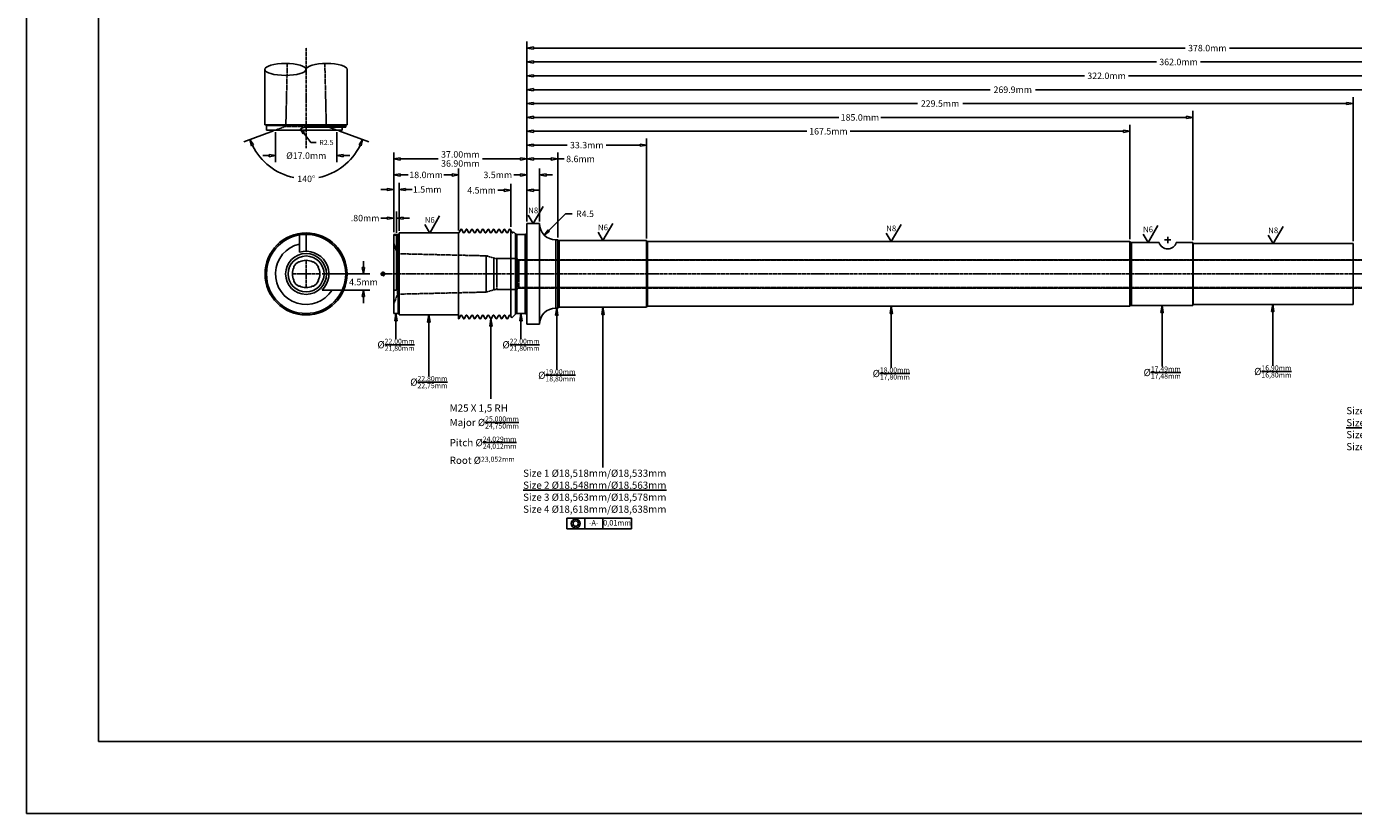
# Model space of a CAD drawing. Units: inches. Extents: x 0 to 594, y 0 to 420.
# Drawn here: x 0 to 369, y 0 to 219 of the extents above; entities that cross this region are included whole.
import ezdxf
from ezdxf.enums import TextEntityAlignment as Align

# ---------------------------------------------------------------- set-up
doc = ezdxf.new("R2010")
doc.units = ezdxf.units.IN
doc.header["$MEASUREMENT"] = 0
doc.linetypes.add('CENTER2', pattern=[1.125, 0.75, -0.125, 0.125, -0.125])
doc.linetypes.add('HIDDEN2', pattern=[0.1875, 0.125, -0.0625])
for name, color, linetype in [('CENTER', 1, 'CENTER2'), ('CENTERLINE', 1, 'CENTER2'), ('HIDDEN', 5, 'HIDDEN2'), ('TEXT', 5, 'Continuous')]:
    doc.layers.add(name, color=color, linetype=linetype)
doc.dimstyles.get("Standard").update_dxf_attribs({"dimscale": 10, "dimtxt": 0.18, "dimasz": 0.18, "dimexe": 0.18, "dimexo": 0.0625, "dimgap": 0.09, "dimtad": 0, "dimtih": 1, "dimtoh": 1, "dimdec": 4, "dimzin": 0, "dimdsep": 46, "dimtxsty": 'Standard', "dimblk": 'CLOSEDBLANK', "dimcen": 0.09, "dimadec": 4, "dimazin": 0, "dimtfac": 1, "dimtdec": 4, "dimtofl": 0, "dimtmove": 0, "dimatfit": 3, "dimldrblk": 'CLOSEDBLANK', "dimfxl": 0, "dimtolj": 1, "dimtzin": 0, "dimarcsym": 0})
doc.dimstyles.new('Standard$0', dxfattribs={"dimscale": 10, "dimtxt": 0.18, "dimasz": 0.18, "dimexe": 0.18, "dimexo": 0.0625, "dimgap": 0.09, "dimtad": 0, "dimtih": 1, "dimtoh": 1, "dimdec": 4, "dimzin": 4, "dimdsep": 46, "dimtxsty": 'Standard', "dimblk": 'CLOSEDBLANK', "dimcen": 0.09, "dimadec": 5, "dimazin": 1, "dimtfac": 1, "dimtdec": 4, "dimtofl": 0, "dimtmove": 0, "dimatfit": 3, "dimldrblk": 'CLOSEDBLANK', "dimfxl": 0, "dimtolj": 1, "dimtzin": 0, "dimarcsym": 0})

# ---------------------------------------------------------------- blocks, each defined once
blk = doc.blocks.new('_ClosedBlank')
at = {"color": 0, "linetype": 'ByBlock', "lineweight": -2}
for p, q in [((-1, 0.17), (0, 0)), ((-1, 0.17), (-1, -0.17)), ((0, 0), (-1, -0.17))]:
    blk.add_line(p, q, dxfattribs=at)
blk = doc.blocks.new('*D20')
at = {"color": 0, "lineweight": -2}
for p, q in [((139, 164.63), (139, 210.74)), ((501, 157.15), (501, 210.74)), ((140.8, 208.94), (313.85, 208.94)), ((499.2, 208.94), (326.15, 208.94))]:
    blk.add_line(p, q, dxfattribs=at)
at = {"layer": 'Defpoints', "color": 0}
for p in [(501, 208.94), (139, 164), (501, 156.53)]:
    blk.add_point(p, dxfattribs=at)
at = {"color": 0, "lineweight": -2, "xscale": 1.8, "yscale": 1.8, "zscale": 1.8, "rotation": 180}
blk.add_blockref('_ClosedBlank', (139, 208.94), dxfattribs=at)
at = {"color": 0, "lineweight": -2, "xscale": 1.8, "yscale": 1.8, "zscale": 1.8}
blk.add_blockref('_ClosedBlank', (501, 208.94), dxfattribs=at)
at = {"color": 0, "insert": (320, 208.94), "char_height": 1.8, "attachment_point": 5}
blk.add_mtext('\\A1;362.0mm', dxfattribs=at)
blk = doc.blocks.new('*D7')
at = {"color": 0, "lineweight": -2}
for p, q in [((102, 161.63), (102, 167.33)), ((102.8, 161.43), (102.8, 167.33)), ((100.2, 165.53), (98.4, 165.53)), ((104.6, 165.53), (106.4, 165.53))]:
    blk.add_line(p, q, dxfattribs=at)
at = {"layer": 'Defpoints', "color": 0}
for p in [(102.8, 165.53), (102, 161), (102.8, 160.8)]:
    blk.add_point(p, dxfattribs=at)
at = {"color": 0, "lineweight": -2, "xscale": 1.8, "yscale": 1.8, "zscale": 1.8}
blk.add_blockref('_ClosedBlank', (102, 165.53), dxfattribs=at)
at = {"color": 0, "lineweight": -2, "xscale": 1.8, "yscale": 1.8, "zscale": 1.8, "rotation": 180}
blk.add_blockref('_ClosedBlank', (102.8, 165.53), dxfattribs=at)
at = {"color": 0, "insert": (94.05, 165.53), "char_height": 1.8, "attachment_point": 5}
blk.add_mtext('\\A1;.80mm', dxfattribs=at)
blk = doc.blocks.new('*D8')
at = {"color": 0, "lineweight": -2}
for p, q in [((100.2, 173.5), (98.4, 173.5)), ((102, 161.63), (102, 175.3)), ((103.5, 162.03), (103.5, 175.3)), ((105.3, 173.5), (107.1, 173.5))]:
    blk.add_line(p, q, dxfattribs=at)
at = {"layer": 'Defpoints', "color": 0}
for p in [(103.5, 173.5), (102, 161), (103.5, 161.4)]:
    blk.add_point(p, dxfattribs=at)
at = {"color": 0, "lineweight": -2, "xscale": 1.8, "yscale": 1.8, "zscale": 1.8}
blk.add_blockref('_ClosedBlank', (102, 173.5), dxfattribs=at)
at = {"color": 0, "lineweight": -2, "xscale": 1.8, "yscale": 1.8, "zscale": 1.8, "rotation": 180}
blk.add_blockref('_ClosedBlank', (103.5, 173.5), dxfattribs=at)
at = {"color": 0, "insert": (111.3, 173.5), "char_height": 1.8, "attachment_point": 5}
blk.add_mtext('\\A1;1.5mm', dxfattribs=at)
blk = doc.blocks.new('*D9')
at = {"color": 0, "lineweight": -2}
for p, q in [((102, 161.63), (102, 179.34)), ((103.8, 177.54), (106.05, 177.54)), ((118.2, 177.54), (115.95, 177.54)), ((120, 162.1), (120, 179.34))]:
    blk.add_line(p, q, dxfattribs=at)
at = {"layer": 'Defpoints', "color": 0}
for p in [(120, 177.54), (102, 161), (120, 161.47)]:
    blk.add_point(p, dxfattribs=at)
at = {"color": 0, "lineweight": -2, "xscale": 1.8, "yscale": 1.8, "zscale": 1.8, "rotation": 180}
blk.add_blockref('_ClosedBlank', (102, 177.54), dxfattribs=at)
at = {"color": 0, "lineweight": -2, "xscale": 1.8, "yscale": 1.8, "zscale": 1.8}
blk.add_blockref('_ClosedBlank', (120, 177.54), dxfattribs=at)
at = {"color": 0, "insert": (111, 177.54), "char_height": 1.8, "attachment_point": 5}
blk.add_mtext('\\A1;18.0mm', dxfattribs=at)
blk = doc.blocks.new('*D10')
at = {"color": 0, "lineweight": -2}
for p, q in [((102, 161.63), (102, 183.78)), ((103.8, 181.98), (114.35, 181.98)), ((137.2, 181.98), (126.65, 181.98)), ((139, 164.63), (139, 183.78))]:
    blk.add_line(p, q, dxfattribs=at)
at = {"layer": 'Defpoints', "color": 0}
for p in [(102, 181.98), (139, 164), (102, 161)]:
    blk.add_point(p, dxfattribs=at)
at = {"color": 0, "lineweight": -2, "xscale": 1.8, "yscale": 1.8, "zscale": 1.8, "rotation": 180}
blk.add_blockref('_ClosedBlank', (102, 181.98), dxfattribs=at)
at = {"color": 0, "lineweight": -2, "xscale": 1.8, "yscale": 1.8, "zscale": 1.8}
blk.add_blockref('_ClosedBlank', (139, 181.98), dxfattribs=at)
at = {"color": 0, "insert": (120.5, 181.98), "char_height": 1.8, "attachment_point": 5}
blk.add_mtext('\\A1;\\S37.00mm^ 36.90mm;', dxfattribs=at)
blk = doc.blocks.new('*D11')
at = {"color": 0, "lineweight": -2}
for p, q in [((137.2, 177.54), (135.4, 177.54)), ((139, 164.63), (139, 179.34)), ((142.5, 164.63), (142.5, 179.34)), ((144.3, 177.54), (146.1, 177.54))]:
    blk.add_line(p, q, dxfattribs=at)
at = {"layer": 'Defpoints', "color": 0}
for p in [(139, 177.54), (139, 164), (142.5, 164)]:
    blk.add_point(p, dxfattribs=at)
at = {"color": 0, "lineweight": -2, "xscale": 1.8, "yscale": 1.8, "zscale": 1.8}
blk.add_blockref('_ClosedBlank', (139, 177.54), dxfattribs=at)
at = {"color": 0, "lineweight": -2, "xscale": 1.8, "yscale": 1.8, "zscale": 1.8, "rotation": 180}
blk.add_blockref('_ClosedBlank', (142.5, 177.54), dxfattribs=at)
at = {"color": 0, "insert": (130.9, 177.54), "char_height": 1.8, "attachment_point": 5}
blk.add_mtext('\\A1;3.5mm', dxfattribs=at)
blk = doc.blocks.new('*D12')
at = {"color": 0, "lineweight": -2}
for p, q in [((139, 164.63), (139, 183.78)), ((140.8, 181.98), (145.78, 181.98)), ((147.58, 160.13), (147.58, 183.78)), ((147.58, 181.98), (149.38, 181.98))]:
    blk.add_line(p, q, dxfattribs=at)
at = {"layer": 'Defpoints', "color": 0}
for p in [(147.58, 181.98), (139, 164), (147.58, 159.5)]:
    blk.add_point(p, dxfattribs=at)
at = {"color": 0, "lineweight": -2, "xscale": 1.8, "yscale": 1.8, "zscale": 1.8, "rotation": 180}
blk.add_blockref('_ClosedBlank', (139, 181.98), dxfattribs=at)
at = {"color": 0, "lineweight": -2, "xscale": 1.8, "yscale": 1.8, "zscale": 1.8}
blk.add_blockref('_ClosedBlank', (147.58, 181.98), dxfattribs=at)
at = {"color": 0, "insert": (153.88, 181.98), "char_height": 1.8, "attachment_point": 5}
blk.add_mtext('\\A1;8.6mm', dxfattribs=at)
blk = doc.blocks.new('*D13')
at = {"color": 0, "lineweight": -2}
for p, q in [((139, 164.63), (139, 187.62)), ((140.8, 185.82), (150.22, 185.82)), ((170.45, 185.82), (161.02, 185.82)), ((172.25, 159.9), (172.25, 187.62))]:
    blk.add_line(p, q, dxfattribs=at)
at = {"layer": 'Defpoints', "color": 0}
for p in [(139, 185.82), (139, 164), (172.25, 159.28)]:
    blk.add_point(p, dxfattribs=at)
at = {"color": 0, "lineweight": -2, "xscale": 1.8, "yscale": 1.8, "zscale": 1.8, "rotation": 180}
blk.add_blockref('_ClosedBlank', (139, 185.82), dxfattribs=at)
at = {"color": 0, "lineweight": -2, "xscale": 1.8, "yscale": 1.8, "zscale": 1.8}
blk.add_blockref('_ClosedBlank', (172.25, 185.82), dxfattribs=at)
at = {"color": 0, "insert": (155.62, 185.82), "char_height": 1.8, "attachment_point": 5}
blk.add_mtext('\\A1;33.3mm', dxfattribs=at)
blk = doc.blocks.new('*D14')
at = {"color": 0, "lineweight": -2}
for p, q in [((139, 164.63), (139, 191.47)), ((140.8, 189.67), (216.75, 189.67)), ((304.7, 189.67), (228.75, 189.67)), ((306.5, 159.63), (306.5, 191.47))]:
    blk.add_line(p, q, dxfattribs=at)
at = {"layer": 'Defpoints', "color": 0}
for p in [(139, 189.67), (139, 164), (306.5, 159)]:
    blk.add_point(p, dxfattribs=at)
at = {"color": 0, "lineweight": -2, "xscale": 1.8, "yscale": 1.8, "zscale": 1.8, "rotation": 180}
blk.add_blockref('_ClosedBlank', (139, 189.67), dxfattribs=at)
at = {"color": 0, "lineweight": -2, "xscale": 1.8, "yscale": 1.8, "zscale": 1.8}
blk.add_blockref('_ClosedBlank', (306.5, 189.67), dxfattribs=at)
at = {"color": 0, "insert": (222.75, 189.67), "char_height": 1.8, "attachment_point": 5}
blk.add_mtext('\\A1;167.5mm', dxfattribs=at)
blk = doc.blocks.new('*D15')
at = {"color": 0, "lineweight": -2}
for p, q in [((139, 164.63), (139, 195.33)), ((140.8, 193.53), (225.65, 193.53)), ((322.2, 193.53), (237.35, 193.53)), ((324, 159.35), (324, 195.33))]:
    blk.add_line(p, q, dxfattribs=at)
at = {"layer": 'Defpoints', "color": 0}
for p in [(139, 193.53), (139, 164), (324, 158.73)]:
    blk.add_point(p, dxfattribs=at)
at = {"color": 0, "lineweight": -2, "xscale": 1.8, "yscale": 1.8, "zscale": 1.8, "rotation": 180}
blk.add_blockref('_ClosedBlank', (139, 193.53), dxfattribs=at)
at = {"color": 0, "lineweight": -2, "xscale": 1.8, "yscale": 1.8, "zscale": 1.8}
blk.add_blockref('_ClosedBlank', (324, 193.53), dxfattribs=at)
at = {"color": 0, "insert": (231.5, 193.53), "char_height": 1.8, "attachment_point": 5}
blk.add_mtext('\\A1;185.0mm', dxfattribs=at)
blk = doc.blocks.new('*D16')
at = {"color": 0, "lineweight": -2}
for p, q in [((139, 164.63), (139, 199.18)), ((368.5, 159.08), (368.5, 199.18)), ((140.8, 197.38), (247.45, 197.38)), ((366.7, 197.38), (260.05, 197.38))]:
    blk.add_line(p, q, dxfattribs=at)
at = {"layer": 'Defpoints', "color": 0}
for p in [(139, 197.38), (139, 164), (368.5, 158.45)]:
    blk.add_point(p, dxfattribs=at)
at = {"color": 0, "lineweight": -2, "xscale": 1.8, "yscale": 1.8, "zscale": 1.8, "rotation": 180}
blk.add_blockref('_ClosedBlank', (139, 197.38), dxfattribs=at)
at = {"color": 0, "lineweight": -2, "xscale": 1.8, "yscale": 1.8, "zscale": 1.8}
blk.add_blockref('_ClosedBlank', (368.5, 197.38), dxfattribs=at)
at = {"color": 0, "insert": (253.75, 197.38), "char_height": 1.8, "attachment_point": 5}
blk.add_mtext('\\A1;229.5mm', dxfattribs=at)
blk = doc.blocks.new('*D17')
at = {"color": 0, "lineweight": -2}
for p, q in [((139, 164.63), (139, 206.89)), ((461, 158.38), (461, 206.89)), ((140.8, 205.09), (293.85, 205.09)), ((459.2, 205.09), (306.15, 205.09))]:
    blk.add_line(p, q, dxfattribs=at)
at = {"layer": 'Defpoints', "color": 0}
for p in [(461, 205.09), (139, 164), (461, 157.75)]:
    blk.add_point(p, dxfattribs=at)
at = {"color": 0, "lineweight": -2, "xscale": 1.8, "yscale": 1.8, "zscale": 1.8, "rotation": 180}
blk.add_blockref('_ClosedBlank', (139, 205.09), dxfattribs=at)
at = {"color": 0, "lineweight": -2, "xscale": 1.8, "yscale": 1.8, "zscale": 1.8}
blk.add_blockref('_ClosedBlank', (461, 205.09), dxfattribs=at)
at = {"color": 0, "insert": (300, 205.09), "char_height": 1.8, "attachment_point": 5}
blk.add_mtext('\\A1;322.0mm', dxfattribs=at)
blk = doc.blocks.new('*D22')
at = {"color": 0, "lineweight": -2}
for p, q in [((93.58, 151.8), (93.58, 153.6)), ((82.08, 150), (95.38, 150)), ((88.31, 145.5), (95.38, 145.5)), ((93.58, 143.7), (93.58, 141.9))]:
    blk.add_line(p, q, dxfattribs=at)
at = {"layer": 'Defpoints', "color": 0}
for p in [(81.46, 150), (93.58, 150), (87.69, 145.5)]:
    blk.add_point(p, dxfattribs=at)
at = {"color": 0, "lineweight": -2, "xscale": 1.8, "yscale": 1.8, "zscale": 1.8}
for p, rotation in [((93.58, 150), 270), ((93.58, 145.5), 90)]:
    blk.add_blockref('_ClosedBlank', p, dxfattribs=dict(at, rotation=rotation))
at = {"color": 0, "insert": (93.58, 147.75), "char_height": 1.8, "attachment_point": 5}
blk.add_mtext('\\A1;4.5mm', dxfattribs=at)
blk = doc.blocks.new('*D23')
at = {"color": 0, "lineweight": -2}
for p, q in [((78.99, 186.56), (77, 189.14)), ((80.43, 186.56), (78.99, 186.56))]:
    blk.add_line(p, q, dxfattribs=at)
at = {"layer": 'Defpoints', "color": 0}
for p in [(76.12, 190.28), (77.65, 188.3)]:
    blk.add_point(p, dxfattribs=at)
at = {"color": 0, "lineweight": -2, "xscale": 1.44, "yscale": 1.44, "zscale": 1.44, "rotation": 127.7379653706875}
blk.add_blockref('_ClosedBlank', (76.12, 190.28), dxfattribs=at)
at = {"color": 0, "insert": (83.31, 186.56), "char_height": 1.44, "attachment_point": 5}
blk.add_mtext('\\A1;R2.5', dxfattribs=at)
blk = doc.blocks.new('*D24')
at = {"color": 0, "lineweight": -2}
for p, q in [((139, 164.63), (139, 203.03)), ((408.9, 158.65), (408.9, 203.03)), ((140.8, 201.23), (267.65, 201.23)), ((407.1, 201.23), (280.25, 201.23))]:
    blk.add_line(p, q, dxfattribs=at)
at = {"layer": 'Defpoints', "color": 0}
for p in [(139, 201.23), (139, 164), (408.9, 158.03)]:
    blk.add_point(p, dxfattribs=at)
at = {"color": 0, "lineweight": -2, "xscale": 1.8, "yscale": 1.8, "zscale": 1.8, "rotation": 180}
blk.add_blockref('_ClosedBlank', (139, 201.23), dxfattribs=at)
at = {"color": 0, "lineweight": -2, "xscale": 1.8, "yscale": 1.8, "zscale": 1.8}
blk.add_blockref('_ClosedBlank', (408.9, 201.23), dxfattribs=at)
at = {"color": 0, "insert": (273.95, 201.23), "char_height": 1.8, "attachment_point": 5}
blk.add_mtext('\\A1;269.9mm', dxfattribs=at)
blk = doc.blocks.new('*D25')
at = {"color": 0, "lineweight": -2}
for p, q in [((139, 164.63), (139, 214.6)), ((517, 157.52), (517, 214.6)), ((140.8, 212.8), (321.85, 212.8)), ((515.2, 212.8), (334.15, 212.8))]:
    blk.add_line(p, q, dxfattribs=at)
at = {"layer": 'Defpoints', "color": 0}
for p in [(517, 212.8), (139, 164), (517, 156.89)]:
    blk.add_point(p, dxfattribs=at)
at = {"color": 0, "lineweight": -2, "xscale": 1.8, "yscale": 1.8, "zscale": 1.8, "rotation": 180}
blk.add_blockref('_ClosedBlank', (139, 212.8), dxfattribs=at)
at = {"color": 0, "lineweight": -2, "xscale": 1.8, "yscale": 1.8, "zscale": 1.8}
blk.add_blockref('_ClosedBlank', (517, 212.8), dxfattribs=at)
at = {"color": 0, "insert": (328, 212.8), "char_height": 1.8, "attachment_point": 5}
blk.add_mtext('\\A1;378.0mm', dxfattribs=at)
blk = doc.blocks.new('*D26')
at = {"color": 0, "lineweight": -2}
for p, q in [((132.7, 173.26), (130.9, 173.26)), ((134.5, 163.13), (134.5, 175.06)), ((139, 164.63), (139, 175.06)), ((140.8, 173.26), (142.6, 173.26))]:
    blk.add_line(p, q, dxfattribs=at)
at = {"layer": 'Defpoints', "color": 0}
for p in [(139, 173.26), (134.5, 162.5), (139, 164)]:
    blk.add_point(p, dxfattribs=at)
at = {"color": 0, "lineweight": -2, "xscale": 1.8, "yscale": 1.8, "zscale": 1.8}
blk.add_blockref('_ClosedBlank', (134.5, 173.26), dxfattribs=at)
at = {"color": 0, "lineweight": -2, "xscale": 1.8, "yscale": 1.8, "zscale": 1.8, "rotation": 180}
blk.add_blockref('_ClosedBlank', (139, 173.26), dxfattribs=at)
at = {"color": 0, "insert": (126.4, 173.26), "char_height": 1.8, "attachment_point": 5}
blk.add_mtext('\\A1;4.5mm', dxfattribs=at)
blk = doc.blocks.new('*D27')
at = {"color": 0, "lineweight": -2}
for p, q in [((149.73, 166.73), (145.09, 162.09)), ((151.53, 166.73), (149.73, 166.73))]:
    blk.add_line(p, q, dxfattribs=at)
at = {"layer": 'Defpoints', "color": 0}
for p in [(147, 164), (143.82, 160.82)]:
    blk.add_point(p, dxfattribs=at)
at = {"color": 0, "lineweight": -2, "xscale": 1.8, "yscale": 1.8, "zscale": 1.8, "rotation": 224.9999999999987}
blk.add_blockref('_ClosedBlank', (143.82, 160.82), dxfattribs=at)
at = {"color": 0, "insert": (155.13, 166.73), "char_height": 1.8, "attachment_point": 5}
blk.add_mtext('\\A1;R4.5', dxfattribs=at)
blk = doc.blocks.new('*D28')
at = {"color": 0, "lineweight": -2}
for p, q in [((68.61, 189.79), (60.36, 186.78)), ((86.79, 189.79), (95.04, 186.78))]:
    blk.add_line(p, q, dxfattribs=at)
for start, end in [(206.197, 258.0416), (281.9584, 333.803)]:
    blk.add_arc((77.7, 193.09), 16.65, start, end, dxfattribs=at)
at = {"layer": 'Defpoints', "color": 0}
for p in [(69.2, 190), (72.03, 191.03), (83.37, 191.03), (86.2, 190), (71.1, 177.81)]:
    blk.add_point(p, dxfattribs=at)
at = {"color": 0, "lineweight": -2, "xscale": 1.8, "yscale": 1.8, "zscale": 1.8}
for p, rotation in [((62.05, 187.4), 113.0985010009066), ((93.35, 187.4), 66.90149899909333)]:
    blk.add_blockref('_ClosedBlank', p, dxfattribs=dict(at, rotation=rotation))
at = {"color": 0, "insert": (77.7, 176.44), "char_height": 1.8, "attachment_point": 5}
blk.add_mtext('\\A1;140°', dxfattribs=at)
blk = doc.blocks.new('*D29')
at = {"color": 0, "lineweight": -2}
for p, q in [((69.2, 189.38), (69.2, 181.1)), ((86.2, 189.38), (86.2, 181.1)), ((67.4, 182.9), (65.6, 182.9)), ((88, 182.9), (89.8, 182.9))]:
    blk.add_line(p, q, dxfattribs=at)
at = {"layer": 'Defpoints', "color": 0}
for p in [(69.2, 190), (86.2, 190), (86.2, 182.9)]:
    blk.add_point(p, dxfattribs=at)
at = {"color": 0, "lineweight": -2, "xscale": 1.8, "yscale": 1.8, "zscale": 1.8}
blk.add_blockref('_ClosedBlank', (69.2, 182.9), dxfattribs=at)
at = {"color": 0, "lineweight": -2, "xscale": 1.8, "yscale": 1.8, "zscale": 1.8, "rotation": 180}
blk.add_blockref('_ClosedBlank', (86.2, 182.9), dxfattribs=at)
at = {"color": 0, "insert": (77.7, 182.9), "char_height": 1.8, "attachment_point": 5}
blk.add_mtext('\\A1;%%C17.0mm', dxfattribs=at)

msp = doc.modelspace()

# ---------------------------------------------------------------- hatches: boundary and pattern name
at = {"layer": 'CENTER'}
h = msp.add_hatch(dxfattribs=at)
h.set_pattern_fill('ANSI31', color=256, style=0)
h.set_pattern_definition([(45, (50, 100), (-0.08838835, 0.08838835), [])])
h.paths.add_polyline_path([(98.99996, 150.50003, 0.414213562), (98.49996, 150.00003), (98.99996, 150.00003)])
h.paths.add_polyline_path([(99.49996, 150.00003), (98.99996, 150.00003), (98.99996, 149.50003, 0.414213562)])

# ---------------------------------------------------------------- linework, layer by layer
for p, q in [((66.21531, 191.50003), (66.21531, 206.86689)), ((89.08461, 191.50003), (89.08461, 206.86689)), ((89.08461, 191.50003), (66.21531, 191.50003)), ((66.64996, 190.00003), (66.64996, 191.25003)), ((88.64996, 191.25003), (66.64996, 191.25003)), ((87.68739, 190.00003), (66.64996, 190.00003)), ((88.64996, 190.80003), (77.64996, 190.80003)), ((83.95198, 190.80003), (86.14996, 190.00003)), ((87.68739, 190.00003), (87.68739, 190.80003)), ((88.64996, 190.80003), (88.64996, 191.25003)), ((111.99996, 161.36503), (114.74959, 166.12753)), ((139.37514, 166.38128), (140.74996, 164.00003)), ((140.74996, 164.00003), (143.49959, 168.76253)), ((110.62514, 163.74628), (111.99996, 161.36503)), ((120.09371, 161.47162), (120.68746, 162.50003)), ((120.65621, 162.4459), (120.68746, 162.50003)), ((120.68746, 162.50003), (120.81246, 162.50003)), ((120.81246, 162.50003), (120.68746, 162.50003)), ((120.81246, 162.50003), (121.40621, 161.47162)), ((121.59371, 161.47162), (122.18746, 162.50003)), ((122.15621, 162.4459), (122.18746, 162.50003)), ((122.18746, 162.50003), (122.31246, 162.50003)), ((122.31246, 162.50003), (122.18746, 162.50003)), ((122.31246, 162.50003), (122.90621, 161.47162)), ((123.09371, 161.47162), (123.68746, 162.50003)), ((123.65621, 162.4459), (123.68746, 162.50003)), ((123.68746, 162.50003), (123.81246, 162.50003)), ((123.81246, 162.50003), (123.68746, 162.50003)), ((123.81246, 162.50003), (124.40621, 161.47162)), ((124.59371, 161.47162), (125.18746, 162.50003)), ((125.18746, 162.50003), (125.31246, 162.50003)), ((125.31246, 162.50003), (125.18746, 162.50003)), ((125.31246, 162.50003), (125.90621, 161.47162)), ((126.09371, 161.47162), (126.68746, 162.50003)), ((126.81246, 162.50003), (126.68746, 162.50003)), ((126.81246, 162.50003), (127.40621, 161.47162)), ((127.59371, 161.47162), (128.18746, 162.50003)), ((128.31246, 162.50003), (128.18746, 162.50003)), ((128.31246, 162.50003), (128.90621, 161.47162)), ((129.09371, 161.47162), (129.68746, 162.50003)), ((129.81246, 162.50003), (129.68746, 162.50003)), ((129.81246, 162.50003), (130.40621, 161.47162)), ((130.59371, 161.47162), (131.18746, 162.50003)), ((131.31246, 162.50003), (131.18746, 162.50003)), ((131.31246, 162.50003), (131.90621, 161.47162)), ((132.09371, 161.47162), (132.68746, 162.50003)), ((132.81246, 162.50003), (132.68746, 162.50003)), ((132.81246, 162.50003), (133.40621, 161.47162)), ((133.59371, 161.47162), (134.18746, 162.50003)), ((134.31246, 162.50003), (134.18746, 162.50003)), ((134.31246, 162.50003), (134.90621, 161.47162)), ((138.99996, 136.00003), (138.99996, 164.00003)), ((138.99996, 164.00003), (142.49996, 164.00003)), ((142.49996, 136.00003), (142.49996, 164.00003)), ((160.12496, 159.27503), (162.87459, 164.03753)), ((240.19588, 159.00003), (242.94551, 163.76253)), ((311.52763, 158.72503), (314.27726, 163.48753)), ((346.29996, 158.45003), (349.04959, 163.21253)), ((75.81693, 156.05965), (75.81693, 160.84623)), ((77.64996, 156.33083), (77.64996, 161.00003)), ((101.99996, 139.00003), (101.99996, 161.00003)), ((101.99996, 161.00003), (103.24996, 161.00003)), ((101.99996, 160.80329), (102.79996, 160.80329)), ((102.79996, 156.30205), (101.99996, 158.50003)), ((102.79996, 145.50003), (102.79996, 160.80329)), ((103.24996, 139.00003), (103.24996, 161.00003)), ((103.49996, 161.40003), (119.99996, 161.40003)), ((103.49996, 138.60003), (103.49996, 161.40003)), ((119.99996, 137.50003), (119.99996, 161.47162)), ((119.99996, 161.47162), (120.09371, 161.47162)), ((121.40621, 161.47162), (121.59371, 161.47162)), ((122.90621, 161.47162), (123.09371, 161.47162)), ((124.40621, 161.47162), (124.59371, 161.47162)), ((125.90621, 161.47162), (126.09371, 161.47162)), ((127.40621, 161.47162), (127.59371, 161.47162)), ((128.90621, 161.47162), (129.09371, 161.47162)), ((130.40621, 161.47162), (130.59371, 161.47162)), ((131.90621, 161.47162), (132.09371, 161.47162)), ((133.40621, 161.47162), (133.59371, 161.47162)), ((134.49996, 138.2578), (134.49996, 162.17527)), ((134.90621, 161.47162), (135.09371, 161.47162)), ((135.09371, 161.47162), (135.25281, 161.74718)), ((135.85351, 161.14648), (135.25281, 161.74718)), ((135.85351, 138.85358), (135.85351, 161.14648)), ((136.20707, 139.00003), (136.20707, 161.00003)), ((136.20707, 161.00003), (138.49996, 161.00003)), ((138.49996, 139.00003), (138.49996, 161.00003)), ((146.99996, 159.50003), (147.58238, 159.50003)), ((146.99996, 159.50003), (146.99996, 140.50003)), ((147.58238, 159.50003), (147.58238, 140.50003)), ((147.99996, 159.27503), (172.24996, 159.27503)), ((147.99996, 140.72503), (147.99996, 159.27503)), ((158.75014, 161.65628), (160.12496, 159.27503)), ((172.24996, 159.27503), (172.24996, 140.72503)), ((172.49996, 159.00003), (306.49996, 159.00003)), ((172.49996, 141.00003), (172.49996, 159.00003)), ((238.82106, 161.38128), (240.19588, 159.00003)), ((306.49996, 159.00003), (306.49996, 141.00003)), ((306.94648, 158.72503), (314.60649, 158.72503)), ((306.94648, 158.72503), (306.94648, 141.27503)), ((310.15281, 161.10628), (311.52763, 158.72503)), ((319.39343, 158.72503), (323.99996, 158.72503)), ((323.99996, 158.72503), (323.99996, 141.27503)), ((344.92514, 160.83128), (346.29996, 158.45003)), ((324.09996, 158.45003), (368.49996, 158.45003)), ((324.09996, 158.45003), (324.09996, 141.55003)), ((368.49996, 158.45003), (368.49996, 141.55003)), ((82.10294, 145.50003), (87.68739, 145.50003)), ((101.99996, 145.50003), (102.79996, 145.50003)), ((146.99996, 140.50003), (147.58238, 140.50003)), ((147.99996, 140.72503), (172.24996, 140.72503)), ((172.49996, 141.00003), (306.49996, 141.00003)), ((306.94648, 141.27503), (323.99996, 141.27503)), ((324.09996, 141.55003), (368.49996, 141.55003)), ((101.99996, 139.00003), (103.24996, 139.00003)), ((103.49996, 138.60003), (119.99996, 138.60003)), ((119.99996, 137.50003), (120.06246, 137.50003)), ((120.06246, 137.50003), (120.65621, 138.52843)), ((120.65621, 138.52843), (120.84371, 138.52843)), ((120.84371, 138.52843), (121.43746, 137.50003)), ((121.40621, 137.55416), (121.43746, 137.50003)), ((121.43746, 137.50003), (121.56246, 137.50003)), ((121.56246, 137.50003), (121.43746, 137.50003)), ((121.56246, 137.50003), (122.15621, 138.52843)), ((122.15621, 138.52843), (122.34371, 138.52843)), ((122.34371, 138.52843), (122.93746, 137.50003)), ((122.90621, 137.55416), (122.93746, 137.50003)), ((122.93746, 137.50003), (123.06246, 137.50003)), ((123.06246, 137.50003), (122.93746, 137.50003)), ((123.06246, 137.50003), (123.65621, 138.52843)), ((123.65621, 138.52843), (123.84371, 138.52843)), ((123.84371, 138.52843), (124.43746, 137.50003)), ((124.40621, 137.55416), (124.43746, 137.50003)), ((124.43746, 137.50003), (124.56246, 137.50003)), ((124.56246, 137.50003), (124.43746, 137.50003)), ((124.56246, 137.50003), (125.15621, 138.52843)), ((125.15621, 138.52843), (125.34371, 138.52843)), ((125.34371, 138.52843), (125.93746, 137.50003)), ((125.93746, 137.50003), (126.06246, 137.50003)), ((126.06246, 137.50003), (125.93746, 137.50003)), ((126.06246, 137.50003), (126.65621, 138.52843)), ((126.65621, 138.52843), (126.84371, 138.52843)), ((126.84371, 138.52843), (127.43746, 137.50003)), ((127.56246, 137.50003), (127.43746, 137.50003)), ((127.56246, 137.50003), (128.15621, 138.52843)), ((128.15621, 138.52843), (128.34371, 138.52843)), ((128.34371, 138.52843), (128.93746, 137.50003)), ((129.06246, 137.50003), (128.93746, 137.50003)), ((129.06246, 137.50003), (129.65621, 138.52843)), ((129.65621, 138.52843), (129.84371, 138.52843)), ((129.84371, 138.52843), (130.43746, 137.50003)), ((130.56246, 137.50003), (130.43746, 137.50003)), ((130.56246, 137.50003), (131.15621, 138.52843)), ((131.15621, 138.52843), (131.34371, 138.52843)), ((131.34371, 138.52843), (131.93746, 137.50003)), ((132.06246, 137.50003), (131.93746, 137.50003)), ((132.06246, 137.50003), (132.65621, 138.52843)), ((132.65621, 138.52843), (132.84371, 138.52843)), ((132.84371, 138.52843), (133.43746, 137.50003)), ((133.56246, 137.50003), (133.43746, 137.50003)), ((133.56246, 137.50003), (134.15621, 138.52843)), ((134.15621, 138.52843), (134.34371, 138.52843)), ((134.34371, 138.52843), (134.77732, 137.77739)), ((135.85351, 138.85358), (134.77732, 137.77739)), ((136.20707, 139.00003), (138.49996, 139.00003)), ((138.99996, 136.00003), (142.49996, 136.00003))]:
    msp.add_line(p, q)
for points in [[(-0.00002, 0.00005), (593.99998, 0.00005), (593.99998, 420.00005), (-0.00002, 420.00005)], [(19.99998, 20.00005), (573.99998, 20.00005), (573.99998, 400.00005), (19.99998, 400.00005)]]:
    msp.add_lwpolyline(points, close=True)
for radius in [11.4, 11, 5.67115, 5]:
    msp.add_circle((77.64996, 150.00003), radius)
for centre, radius, start, end in [((66.39996, 191.25003), 0.25, 0, 90), ((77.64996, 188.30003), 2.5, 90, 137.156357), ((88.89996, 191.25003), 0.25, 90, 180), ((146.99996, 164.00003), 4.5, 180, 270), ((103.24996, 161.25003), 0.25, 270, 0), ((136.20707, 161.50003), 0.5, 225, 270), ((138.49996, 161.50003), 0.5, 270, 4.0139872), ((147.99996, 159.77503), 0.5, 213.367013, 270), ((172.49996, 159.25003), 0.25, 180, 270), ((306.94648, 159.22503), 0.5, 206.7437386, 270), ((316.99996, 159.44703), 2.5, 196.7861274, 343.2138726), ((324.09996, 158.55003), 0.1, 180, 270), ((77.64996, 150.00003), 8.5, 102.4537006, 328.0342812), ((77.64996, 150.00003), 6.3308, 314.6990904, 106.8305173), ((368.59996, 158.12503), 0.1, 180, 270), ((146.99996, 136.00003), 4.5, 90, 180), ((147.99996, 140.22503), 0.5, 90, 146.632987), ((172.49996, 140.75003), 0.25, 90, 180), ((306.94648, 140.77503), 0.5, 89.999979, 153.2563616), ((324.09996, 141.45003), 0.1, 90, 180), ((368.59996, 141.87503), 0.1, 90, 180), ((103.24996, 138.75003), 0.25, 0, 90), ((136.20707, 138.50003), 0.5, 90, 135), ((138.49996, 138.50003), 0.5, 355.9860128, 90)]:
    msp.add_arc(centre, radius, start, end)
at = {"ltscale": 0.25}
for centre, radius, start, end in [((77.64996, 150.00003), 3.81, 151.3407406, 208.6592594), ((74.3825, 151.95957), 0.1524, 149.0482979, 240.1945192), ((77.64996, 150.00003), 3.9624, 120.9517021, 149.0482979), ((75.69042, 153.26749), 0.1524, 29.8054808, 120.9517021), ((77.64996, 150.00003), 3.81, 61.3407406, 118.6592594), ((79.6095, 153.26749), 0.1524, 59.0482979, 150.1945192), ((77.64996, 150.00003), 3.9624, 30.9517021, 59.0482979), ((80.91742, 151.95957), 0.1524, 299.8054808, 30.9517021), ((77.64996, 150.00003), 3.81, 331.3407406, 28.6592594), ((74.3825, 148.04049), 0.1524, 119.8054808, 210.9517021), ((77.64996, 150.00003), 3.9624, 210.9517021, 239.0482979), ((77.64996, 150.00003), 3.9624, 300.9517021, 329.0482979), ((80.91742, 148.04049), 0.1524, 329.0482979, 60.1945192), ((75.69042, 146.73257), 0.1524, 239.0482979, 330.1945192), ((77.64996, 150.00003), 3.81, 241.3407406, 298.6592594), ((79.6095, 146.73257), 0.1524, 209.8054808, 300.9517021)]:
    msp.add_arc(centre, radius, start, end, dxfattribs=at)
msp.add_ellipse((71.93264, 206.86689), major_axis=(-5.71732, 0), ratio=0.291449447)
msp.add_ellipse((83.36728, 206.86689), major_axis=(-5.71732, 0), ratio=0.291449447, start_param=3.141592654, end_param=6.283185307)
at = {"layer": 'CENTER'}
for p, q in [((316.09996, 159.44703), (317.89996, 159.44703)), ((316.99996, 158.54703), (316.99996, 160.34703)), ((98.99996, 149.50003), (98.99996, 150.50003))]:
    msp.add_line(p, q, dxfattribs=at)
msp.add_circle((98.99996, 150.00003), 0.5, dxfattribs=at)
at = {"layer": 'CENTERLINE'}
for p, q in [((77.64996, 185.00003), (77.64996, 212.89728)), ((77.64996, 146.19003), (77.64996, 153.81003)), ((73.83996, 150.00003), (81.45996, 150.00003)), ((98.49996, 150.00003), (518.99996, 150.00003))]:
    msp.add_line(p, q, dxfattribs=at)
at = {"layer": 'HIDDEN'}
for p, q in [((72.02852, 191.02964), (72.43902, 208.53998)), ((83.2714, 191.02964), (82.8609, 208.53998)), ((71.97879, 191.02964), (69.14996, 190.00003)), ((83.32113, 191.02964), (71.97879, 191.02964)), ((83.32113, 191.02964), (83.95198, 190.80003)), ((103.02957, 155.6712), (102.79996, 156.30205)), ((103.02957, 144.32886), (103.02957, 155.6712)), ((103.02957, 155.62147), (127.66907, 155.04384)), ((127.66907, 144.95615), (127.66907, 155.04384)), ((127.66907, 155.04384), (129.78483, 154.42181)), ((129.78483, 145.57819), (129.78483, 154.42181)), ((130.63101, 154.3), (136.24493, 154.3)), ((130.63101, 145.7), (130.63101, 154.3)), ((136.24493, 145.7), (136.24493, 154.3)), ((136.24493, 154.3), (136.7349, 153.81003)), ((136.5825, 153.96243), (516.99996, 153.96243)), ((136.7349, 153.81003), (516.99996, 153.81003)), ((136.73496, 146.19003), (136.73496, 153.81003)), ((103.02957, 144.32886), (101.99996, 141.50003)), ((103.02957, 144.37859), (127.66907, 144.95622)), ((127.66907, 144.95615), (129.78483, 145.57819)), ((130.63101, 145.7), (136.24493, 145.7)), ((136.24493, 145.7), (136.73496, 146.19003)), ((136.58256, 146.03763), (516.99996, 146.03763)), ((136.73496, 146.19003), (516.99996, 146.19003))]:
    msp.add_line(p, q, dxfattribs=at)
for centre, start, end in [((130.63101, 157.3), 253.6167, 270), ((130.63101, 142.7), 90, 106.3833)]:
    msp.add_arc(centre, 3, start, end, dxfattribs=at)
msp.add_point((128.04493, 155.03503), dxfattribs=at)
at = {"layer": 'TEXT', "color": 7}
for p, q in [((150.04924, 79.1172), (150.04924, 82.1172)), ((150.04924, 82.1172), (155.04924, 82.1172)), ((155.04924, 82.1172), (160.04924, 82.1172)), ((155.04924, 79.1172), (155.04924, 82.1172)), ((160.04924, 82.1172), (168.04924, 82.1172)), ((160.04924, 79.1172), (160.04924, 82.1172)), ((168.04924, 79.1172), (168.04924, 82.1172)), ((150.04924, 79.1172), (155.04924, 79.1172)), ((155.04924, 79.1172), (160.04924, 79.1172)), ((160.04924, 79.1172), (168.04924, 79.1172))]:
    msp.add_line(p, q, dxfattribs=at)
for radius in [1.25, 0.75]:
    msp.add_circle((152.54924, 80.6172), radius, dxfattribs=at)

# ---------------------------------------------------------------- texts
for s, p in [('N8', (140.74996, 166.38128)), ('N6', (111.99996, 163.74628)), ('N6', (160.12496, 161.65628)), ('N8', (240.19588, 161.38128)), ('N6', (311.52763, 161.10628)), ('N8', (346.29996, 160.83128))]:
    msp.add_text(s, height=1.5875).set_placement(p, align=Align.BOTTOM_CENTER)
at = {"char_height": 2, "width": 10.5482646, "attachment_point": 2}
for s, insert in [('\\A1;%%C{\\H0.7x;\\S22,00mm/21,80mm;}', (102.62496, 132.00003)), ('\\A1;%%C{\\H0.7x;\\S22,00mm/21,80mm;}', (137.35351, 132.00003)), ('\\A1;%%C{\\H0.7x;\\S19,00mm/18,80mm;}', (147.29117, 123.50003)), ('\\A1;%%C{\\H0.7x;\\S18,00mm/17,80mm;}', (240.1946, 124.00003)), ('\\A1;%%C{\\H0.7x;\\S17,49mm/17,48mm;}', (315.44996, 124.27503)), ('\\A1;%%C{\\H0.7x;\\S16,90mm/16,80mm;}', (346.18449, 124.57003)), ('\\A1;%%C{\\H0.7x;\\S22,80mm/22,75mm;}', (111.74996, 121.60003))]:
    msp.add_mtext(s, dxfattribs=dict(at, insert=insert))
at = {"layer": 'TEXT', "color": 7}
for s, insert, char_height, width, attachment_point in [('\\A1;M25 X 1,5 RH\\PMajor %%C{\\H0.7x;\\S25,000mm/24,750mm;}\\PPitch %%C{\\H0.7x;\\S24,029mm/24,012mm;}\\PRoot %%C{\\H0.7x;23,052mm}', (117.54546, 113.72444), 2, 24.8698244, 1), ('\\A1;Size 1 %%C16,018mm/%%C16,033mm\\P{\\LSize 2 %%C16,048mm/%%C16,063mm}\\PSize 3 %%C16,063mm/%%C16,078mm\\PSize 4 %%C16,118mm/%%C16,138mm', (366.61639, 113), 2, 48.5376086, 1), ('\\A1;Size 1 %%C18,518mm/%%C18,533mm\\P{\\LSize 2 %%C18,548mm/%%C18,563mm}\\PSize 3 %%C18,563mm/%%C18,578mm\\PSize 4 %%C18,618mm/%%C18,638mm', (137.94139, 95.60018), 2, 48.5376086, 1), ('-A-', (157.54924, 80.6172), 1.5, 1.19634, 5), ('0,01mm', (164.04924, 80.6172), 1.5, 6.6720954, 5)]:
    msp.add_mtext(s, dxfattribs=dict(at, insert=insert, char_height=char_height, width=width, attachment_point=attachment_point))

# ---------------------------------------------------------------- dimensions: what is measured, and where the dimension line sits
for base, p1, p2, override, picture, middle in [((516.99996, 212.7953), (138.99996, 164.00003), (516.99996, 156.89178), {"dimscale": 10, "dimdec": 1, "dimpost": 'mm', "dimblk1": 'ClosedBlank', "dimblk2": 'ClosedBlank', "dimsah": 1}, '*D25', (327.99996, 212.7953)), ((500.99996, 208.94125), (138.99996, 164.00003), (500.99996, 156.52503), {"dimscale": 10, "dimdec": 1, "dimpost": 'mm', "dimblk1": 'ClosedBlank', "dimblk2": 'ClosedBlank', "dimsah": 1}, '*D20', (319.99996, 208.94125)), ((460.99996, 205.08719), (138.99996, 164.00003), (460.99996, 157.75003), {"dimscale": 10, "dimdec": 1, "dimpost": 'mm', "dimblk1": 'ClosedBlank', "dimblk2": 'ClosedBlank', "dimsah": 1}, '*D17', (299.99996, 205.08719)), ((138.99996, 201.23314), (408.89996, 158.02503), (138.99996, 164.00003), {"dimscale": 10, "dimdec": 1, "dimpost": 'mm', "dimblk1": 'ClosedBlank', "dimblk2": 'ClosedBlank', "dimsah": 1}, '*D24', (273.94996, 201.23314)), ((138.99996, 197.37908), (368.49996, 158.45003), (138.99996, 164.00003), {"dimscale": 10, "dimdec": 1, "dimpost": 'mm', "dimblk1": 'ClosedBlank', "dimblk2": 'ClosedBlank', "dimsah": 1}, '*D16', (253.74996, 197.37908)), ((138.99996, 193.52503), (323.99996, 158.72503), (138.99996, 164.00003), {"dimscale": 10, "dimdec": 1, "dimpost": 'mm', "dimblk1": 'ClosedBlank', "dimblk2": 'ClosedBlank', "dimsah": 1}, '*D15', (231.49996, 193.52503)), ((138.99996, 189.67097), (306.49996, 159.00003), (138.99996, 164.00003), {"dimscale": 10, "dimdec": 1, "dimpost": 'mm', "dimblk1": 'ClosedBlank', "dimblk2": 'ClosedBlank', "dimsah": 1}, '*D14', (222.74996, 189.67097)), ((138.999960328, 185.8169208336), (172.249960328, 159.2750289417), (138.999960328, 164.0000289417), {"dimscale": 10, "dimdec": 1, "dimpost": 'mm', "dimblk1": 'ClosedBlank', "dimblk2": 'ClosedBlank', "dimsah": 1}, '*D13', (155.624960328, 185.8169208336)), ((101.99996, 181.97503), (138.99996, 164.00003), (101.99996, 161.00003), {"dimdec": 2, "dimpost": 'mm', "dimblk1": 'ClosedBlank', "dimblk2": 'ClosedBlank', "dimsah": 1, "dimlim": 1, "dimtm": 0.1, "dimtdec": 2}, '*D10', (120.49996, 181.97503)), ((147.58238, 181.97503), (138.99996, 164.00003), (147.58238, 159.50003), {"dimscale": 10, "dimdec": 1, "dimpost": 'mm', "dimblk1": 'ClosedBlank', "dimblk2": 'ClosedBlank', "dimsah": 1}, '*D12', (153.88238, 181.97503)), ((119.99996, 177.53503), (101.99996, 161.00003), (119.99996, 161.47162), {"dimscale": 10, "dimdec": 1, "dimpost": 'mm', "dimblk1": 'ClosedBlank', "dimblk2": 'ClosedBlank', "dimsah": 1}, '*D9', (110.99996, 177.53503)), ((138.99996, 177.53503), (142.49996, 164.00003), (138.99996, 164.00003), {"dimscale": 10, "dimdec": 1, "dimpost": 'mm', "dimblk1": 'ClosedBlank', "dimblk2": 'ClosedBlank', "dimsah": 1}, '*D11', (130.89996, 177.53503)), ((103.49996, 173.50003), (101.99996, 161.00003), (103.49996, 161.40003), {"dimscale": 10, "dimdec": 1, "dimpost": 'mm', "dimblk1": 'ClosedBlank', "dimblk2": 'ClosedBlank', "dimsah": 1}, '*D8', (111.29996, 173.50003))]:
    dim = msp.add_linear_dim(base=base, p1=p1, p2=p2, dimstyle='Standard$0', override=override)
    dim.commit()
    dim.dimension.update_dxf_attribs({"geometry": picture, "text_midpoint": middle})
dim = msp.add_angular_dim_2l(base=(71.1048, 177.80509), line1=((83.37086, 191.02964), (86.19969, 190.00003)), line2=((72.02852, 191.02964), (69.19969, 190.00003)), dimstyle='Standard', override={"dimadec": 0})
dim.commit()
dim.dimension.update_dxf_attribs({"geometry": '*D28', "text_midpoint": (77.69969, 176.44336)})
dim = msp.add_linear_dim(base=(86.19969, 182.90275), p1=(69.19969, 190.00003), p2=(86.19969, 190.00003), text='%%C<>', dimstyle='Standard$0', override={"dimdec": 1, "dimpost": 'mm'})
dim.commit()
dim.dimension.update_dxf_attribs({"geometry": '*D29', "text_midpoint": (77.69969, 182.90275)})
for center, mpoint, override, picture, middle in [((77.64996, 188.30003), (76.11983, 190.27707), {"dimscale": 8, "dimdec": 1, "dimtmove": 1}, '*D23', (78.99376, 186.56374)), ((146.99996, 164.00003), (143.81798, 160.81805), {"dimdec": 1, "dimtmove": 1}, '*D27', (149.72608, 166.72615))]:
    dim = msp.add_radius_dim(center=center, mpoint=mpoint, dimstyle='Standard', override=override)
    dim.commit()
    dim.dimension.update_dxf_attribs({"geometry": picture, "text_midpoint": middle, "dimtype": 164})
for base, p1, p2, override, picture, middle in [((138.99996, 173.25997), (134.49996, 162.50003), (138.99996, 164.00003), {"dimscale": 10, "dimdec": 1, "dimpost": 'mm', "dimblk1": 'ClosedBlank', "dimblk2": 'ClosedBlank', "dimsah": 1}, '*D26', (126.39996, 173.25997)), ((102.79996, 165.52503), (101.99996, 161.00003), (102.79996, 160.80329), {"dimscale": 10, "dimdec": 2, "dimpost": 'mm', "dimblk1": 'ClosedBlank', "dimblk2": 'ClosedBlank', "dimsah": 1}, '*D7', (94.04996, 165.52503))]:
    dim = msp.add_linear_dim(base=base, p1=p1, p2=p2, dimstyle='Standard$0', override=override)
    dim.commit()
    dim.dimension.update_dxf_attribs({"geometry": picture, "text_midpoint": middle, "dimtype": 160})
dim = msp.add_linear_dim(base=(93.58374, 150.00003), p1=(87.68739, 145.50003), p2=(81.45996, 150.00003), angle=90, dimstyle='Standard$0', override={"dimdec": 1, "dimpost": 'mm'})
dim.commit()
dim.dimension.update_dxf_attribs({"geometry": '*D22', "text_midpoint": (93.58374, 147.75003)})

# ---------------------------------------------------------------- leaders
for points in [[(147.29117, 140.50003), (147.29117, 123.50003)], [(240.1946, 141.00003), (240.1946, 124.00003)], [(315.44996, 141.27503), (315.44996, 124.27503)], [(346.18449, 141.57003), (346.18449, 124.57003)], [(102.62496, 139.00003), (102.62496, 132.00003)], [(111.74996, 138.60003), (111.74996, 121.60003)], [(137.35351, 139.00003), (137.35351, 132.00003)]]:
    msp.add_leader(points, dimstyle='Standard', override={"dimscale": 1, "dimasz": 2, "dimgap": 0.09, "dimtad": 0, "dimldrblk": 'ClosedBlank'})
for points in [[(160.12496, 140.72503), (160.12496, 96.20279)], [(128.99996, 137.50003), (128.99996, 115.23891)]]:
    msp.add_leader(points, dimstyle='Standard', override={"dimscale": 1, "dimasz": 2, "dimgap": 0.09, "dimtad": 0, "dimldrblk": 'ClosedBlank'}, dxfattribs=at)

doc.saveas('drawing.dxf')
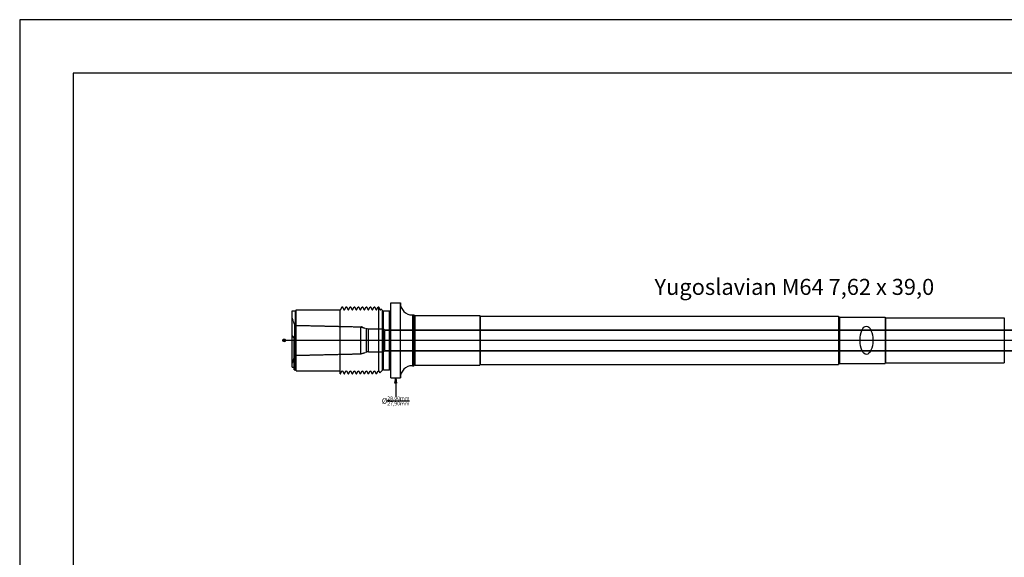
# Model space of a CAD drawing. Units: inches. Extents: x 0 to 594, y 0 to 420.
# Drawn here: x 0 to 369, y 219 to 420 of the extents above; entities that cross this region are included whole.
import ezdxf
from ezdxf.enums import TextEntityAlignment as Align

# ---------------------------------------------------------------- set-up
doc = ezdxf.new("R2010")
doc.units = ezdxf.units.IN
doc.header["$MEASUREMENT"] = 0
doc.linetypes.add('CENTER2', pattern=[1.125, 0.75, -0.125, 0.125, -0.125])
doc.linetypes.add('HIDDEN2', pattern=[0.1875, 0.125, -0.0625])
for name, color, linetype in [('CENTER', 1, 'CENTER2'), ('CENTERLINE', 1, 'CENTER2'), ('HIDDEN', 5, 'HIDDEN2')]:
    doc.layers.add(name, color=color, linetype=linetype)
doc.dimstyles.get("Standard").update_dxf_attribs({"dimscale": 10, "dimtxt": 0.18, "dimasz": 0.18, "dimexe": 0.18, "dimexo": 0.0625, "dimgap": 0.09, "dimtad": 0, "dimtih": 1, "dimtoh": 1, "dimdec": 4, "dimzin": 0, "dimdsep": 46, "dimtxsty": 'Standard', "dimblk": 'CLOSEDBLANK', "dimcen": 0.09, "dimadec": 4, "dimazin": 0, "dimtfac": 1, "dimtdec": 4, "dimtofl": 0, "dimtmove": 0, "dimatfit": 3, "dimldrblk": 'CLOSEDBLANK', "dimfxl": 0, "dimtolj": 1, "dimtzin": 0, "dimarcsym": 0})

# ---------------------------------------------------------------- blocks, each defined once
blk = doc.blocks.new('_ClosedBlank')
at = {"color": 0, "linetype": 'ByBlock', "lineweight": -2}
for p, q in [((-1, 0.17), (0, 0)), ((-1, 0.17), (-1, -0.17)), ((0, 0), (-1, -0.17))]:
    blk.add_line(p, q, dxfattribs=at)

msp = doc.modelspace()

# ---------------------------------------------------------------- hatches: boundary and pattern name
at = {"layer": 'CENTER'}
h = msp.add_hatch(dxfattribs=at)
h.set_pattern_fill('ANSI31', color=256, style=0)
h.set_pattern_definition([(45, (49.99998, 250), (-0.08838835, 0.08838835), [])])
h.paths.add_polyline_path([(98.99994, 300.50003, 0.414213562), (98.49994, 300.00003), (98.99994, 300.00003)])
h.paths.add_polyline_path([(99.49994, 300.00003), (98.99994, 300.00003), (98.99994, 299.50003, 0.414213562)])

# ---------------------------------------------------------------- linework, layer by layer
for p, q in [((138.99994, 286.00003), (138.99994, 314.00003)), ((138.99994, 314.00003), (142.49994, 314.00003)), ((142.49994, 286.00003), (142.49994, 314.00003)), ((101.99994, 289.9626), (101.99994, 311.00003)), ((101.99994, 311.00003), (103.24994, 311.00003)), ((103.24994, 289.00003), (103.24994, 311.00003)), ((103.49994, 311.40003), (119.99994, 311.40003)), ((103.49994, 288.60003), (103.49994, 311.40003)), ((119.99994, 287.50003), (119.99994, 311.47162)), ((119.99994, 311.47162), (120.09369, 311.47162)), ((120.09369, 311.47162), (120.68744, 312.50003)), ((120.65619, 312.4459), (120.68744, 312.50003)), ((120.68744, 312.50003), (120.81244, 312.50003)), ((120.81244, 312.50003), (120.68744, 312.50003)), ((120.81244, 312.50003), (121.40619, 311.47162)), ((121.40619, 311.47162), (121.59369, 311.47162)), ((121.59369, 311.47162), (122.18744, 312.50003)), ((122.15619, 312.4459), (122.18744, 312.50003)), ((122.18744, 312.50003), (122.31244, 312.50003)), ((122.31244, 312.50003), (122.18744, 312.50003)), ((122.31244, 312.50003), (122.90619, 311.47162)), ((122.90619, 311.47162), (123.09369, 311.47162)), ((123.09369, 311.47162), (123.68744, 312.50003)), ((123.65619, 312.4459), (123.68744, 312.50003)), ((123.68744, 312.50003), (123.81244, 312.50003)), ((123.81244, 312.50003), (123.68744, 312.50003)), ((123.81244, 312.50003), (124.40619, 311.47162)), ((124.40619, 311.47162), (124.59369, 311.47162)), ((124.59369, 311.47162), (125.18744, 312.50003)), ((125.18744, 312.50003), (125.31244, 312.50003)), ((125.31244, 312.50003), (125.18744, 312.50003)), ((125.31244, 312.50003), (125.90619, 311.47162)), ((125.90619, 311.47162), (126.09369, 311.47162)), ((126.09369, 311.47162), (126.68744, 312.50003)), ((126.81244, 312.50003), (126.68744, 312.50003)), ((126.81244, 312.50003), (127.40619, 311.47162)), ((127.40619, 311.47162), (127.59369, 311.47162)), ((127.59369, 311.47162), (128.18744, 312.50003)), ((128.31244, 312.50003), (128.18744, 312.50003)), ((128.31244, 312.50003), (128.90619, 311.47162)), ((128.90619, 311.47162), (129.09369, 311.47162)), ((129.09369, 311.47162), (129.68744, 312.50003)), ((129.81244, 312.50003), (129.68744, 312.50003)), ((129.81244, 312.50003), (130.40619, 311.47162)), ((130.40619, 311.47162), (130.59369, 311.47162)), ((130.59369, 311.47162), (131.18744, 312.50003)), ((131.31244, 312.50003), (131.18744, 312.50003)), ((131.31244, 312.50003), (131.90619, 311.47162)), ((131.90619, 311.47162), (132.09369, 311.47162)), ((132.09369, 311.47162), (132.68744, 312.50003)), ((132.81244, 312.50003), (132.68744, 312.50003)), ((132.81244, 312.50003), (133.40619, 311.47162)), ((133.40619, 311.47162), (133.59369, 311.47162)), ((133.59369, 311.47162), (134.18744, 312.50003)), ((134.31244, 312.50003), (134.18744, 312.50003)), ((134.31244, 312.50003), (134.90619, 311.47162)), ((134.49994, 288.2578), (134.49994, 312.17527)), ((134.90619, 311.47162), (135.09369, 311.47162)), ((135.09369, 311.47162), (135.25278, 311.74718)), ((135.85349, 311.14648), (135.25278, 311.74718)), ((135.85349, 288.85358), (135.85349, 311.14648)), ((136.20704, 311.00003), (138.49994, 311.00003)), ((136.20704, 289.00003), (136.20704, 311.00003)), ((138.49994, 289.00003), (138.49994, 311.00003)), ((146.99994, 309.50003), (147.58235, 309.50003)), ((146.99994, 309.50003), (146.99994, 290.50003)), ((147.58235, 309.50003), (147.58235, 290.50003)), ((147.99994, 309.27503), (172.24994, 309.27503)), ((147.99994, 290.72503), (147.99994, 309.27503)), ((172.24994, 309.27503), (172.24994, 290.72503)), ((172.49994, 309.00003), (306.49994, 309.00003)), ((172.49994, 291.00003), (172.49994, 309.00003)), ((306.49994, 309.00003), (306.49994, 291.00003)), ((306.94645, 308.72503), (323.99994, 308.72503)), ((306.94645, 308.72503), (306.94645, 291.27503)), ((323.99994, 308.72503), (323.99994, 291.27503)), ((324.09994, 308.45003), (368.49994, 308.45003)), ((324.09994, 308.45003), (324.09994, 291.55003)), ((368.49994, 308.45003), (368.49994, 291.55003)), ((102.79994, 289.00003), (102.79994, 300.00003)), ((102.79994, 293.69801), (101.99994, 291.50003)), ((306.94645, 291.27503), (323.99994, 291.27503)), ((324.09994, 291.55003), (368.49994, 291.55003)), ((101.99994, 289.9626), (102.79994, 289.9626)), ((102.79994, 289.00003), (103.24994, 289.00003)), ((103.49994, 288.60003), (119.99994, 288.60003)), ((120.06244, 287.50003), (120.65619, 288.52843)), ((120.65619, 288.52843), (120.84369, 288.52843)), ((120.84369, 288.52843), (121.43744, 287.50003)), ((121.40619, 287.55416), (121.43744, 287.50003)), ((121.56244, 287.50003), (122.15619, 288.52843)), ((122.15619, 288.52843), (122.34369, 288.52843)), ((122.34369, 288.52843), (122.93744, 287.50003)), ((122.90619, 287.55416), (122.93744, 287.50003)), ((123.06244, 287.50003), (123.65619, 288.52843)), ((123.65619, 288.52843), (123.84369, 288.52843)), ((123.84369, 288.52843), (124.43744, 287.50003)), ((124.40619, 287.55416), (124.43744, 287.50003)), ((124.56244, 287.50003), (125.15619, 288.52843)), ((125.15619, 288.52843), (125.34369, 288.52843)), ((125.34369, 288.52843), (125.93744, 287.50003)), ((126.06244, 287.50003), (126.65619, 288.52843)), ((126.65619, 288.52843), (126.84369, 288.52843)), ((126.84369, 288.52843), (127.43744, 287.50003)), ((127.56244, 287.50003), (128.15619, 288.52843)), ((128.15619, 288.52843), (128.34369, 288.52843)), ((128.34369, 288.52843), (128.93744, 287.50003)), ((129.06244, 287.50003), (129.65619, 288.52843)), ((129.65619, 288.52843), (129.84369, 288.52843)), ((129.84369, 288.52843), (130.43744, 287.50003)), ((130.56244, 287.50003), (131.15619, 288.52843)), ((131.15619, 288.52843), (131.34369, 288.52843)), ((131.34369, 288.52843), (131.93744, 287.50003)), ((132.06244, 287.50003), (132.65619, 288.52843)), ((132.65619, 288.52843), (132.84369, 288.52843)), ((132.84369, 288.52843), (133.43744, 287.50003)), ((133.56244, 287.50003), (134.15619, 288.52843)), ((134.15619, 288.52843), (134.34369, 288.52843)), ((134.34369, 288.52843), (134.7773, 287.77739)), ((135.85349, 288.85358), (134.7773, 287.77739)), ((136.20704, 289.00003), (138.49994, 289.00003)), ((146.99994, 290.50003), (147.58235, 290.50003)), ((147.99994, 290.72503), (172.24994, 290.72503)), ((172.49994, 291.00003), (306.49994, 291.00003)), ((119.99994, 287.50003), (120.06244, 287.50003)), ((121.43744, 287.50003), (121.56244, 287.50003)), ((121.56244, 287.50003), (121.43744, 287.50003)), ((122.93744, 287.50003), (123.06244, 287.50003)), ((123.06244, 287.50003), (122.93744, 287.50003)), ((124.43744, 287.50003), (124.56244, 287.50003)), ((124.56244, 287.50003), (124.43744, 287.50003)), ((125.93744, 287.50003), (126.06244, 287.50003)), ((126.06244, 287.50003), (125.93744, 287.50003)), ((127.56244, 287.50003), (127.43744, 287.50003)), ((129.06244, 287.50003), (128.93744, 287.50003)), ((130.56244, 287.50003), (130.43744, 287.50003)), ((132.06244, 287.50003), (131.93744, 287.50003)), ((133.56244, 287.50003), (133.43744, 287.50003)), ((138.99994, 286.00003), (142.49994, 286.00003))]:
    msp.add_line(p, q)
for points in [[(-0.00002, 0.00005), (593.99998, 0.00005), (593.99998, 420.00005), (-0.00002, 420.00005)], [(19.99998, 20.00005), (573.99998, 20.00005), (573.99998, 400.00005), (19.99998, 400.00005)]]:
    msp.add_lwpolyline(points, close=True)
for centre, radius, start, end in [((146.99994, 314.00003), 4.5, 180, 270), ((103.24994, 311.25003), 0.25, 270, 0), ((136.20704, 311.50003), 0.5, 225, 270), ((138.49994, 311.50003), 0.5, 270, 4.0139872), ((147.99994, 309.77503), 0.5, 213.367013, 270), ((172.49994, 309.25003), 0.25, 180, 270), ((306.94645, 309.22503), 0.5, 206.7437386, 270), ((324.09994, 308.55003), 0.1, 180, 270), ((368.59994, 308.12503), 0.1, 180, 270), ((100.29994, 300.00003), 2.5, 0, 47.156357), ((306.94645, 290.77503), 0.5, 89.999979, 153.2563616), ((324.09994, 291.45003), 0.1, 90, 180), ((368.59994, 291.87503), 0.1, 90, 180), ((103.24994, 288.75003), 0.25, 0, 90), ((136.20704, 288.50003), 0.5, 90, 135), ((138.49994, 288.50003), 0.5, 355.9860128, 90), ((146.99994, 286.00003), 4.5, 90, 180), ((147.99994, 290.22503), 0.5, 90, 146.632987), ((172.49994, 290.75003), 0.25, 90, 180)]:
    msp.add_arc(centre, radius, start, end)
msp.add_ellipse((316.99994, 300.00003), major_axis=(0, -5.27871), ratio=0.453419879)
msp.add_line((98.99994, 299.50003), (98.99994, 300.50003), dxfattribs=at)
msp.add_circle((98.99994, 300.00003), 0.5, dxfattribs=at)
at = {"layer": 'CENTERLINE'}
msp.add_line((98.49994, 300.00003), (518.99998, 300.00003), dxfattribs=at)
at = {"layer": 'HIDDEN'}
for p, q in [((103.02955, 305.6712), (101.99994, 308.50003)), ((103.02955, 294.32886), (103.02955, 305.6712)), ((103.02955, 305.62147), (127.66904, 305.04384)), ((127.66904, 294.95615), (127.66904, 305.04384)), ((127.66904, 305.04384), (129.7848, 304.42181)), ((129.7848, 295.57819), (129.7848, 304.42181)), ((130.63099, 304.3), (136.2449, 304.3)), ((130.63099, 295.7), (130.63099, 304.3)), ((136.2449, 295.7), (136.2449, 304.3)), ((136.2449, 304.3), (136.73487, 303.81003)), ((136.58247, 303.96243), (516.99994, 303.96243)), ((136.73487, 303.81003), (516.99994, 303.81003)), ((136.73494, 296.19003), (136.73494, 303.81003)), ((103.02955, 294.37859), (127.66904, 294.95622)), ((127.66904, 294.95615), (129.7848, 295.57819)), ((130.63099, 295.7), (136.2449, 295.7)), ((136.2449, 295.7), (136.73494, 296.19003)), ((136.58254, 296.03763), (516.99994, 296.03763)), ((136.73494, 296.19003), (516.99994, 296.19003)), ((103.02955, 294.32886), (102.79994, 293.69801))]:
    msp.add_line(p, q, dxfattribs=at)
for centre, start, end in [((130.63099, 307.3), 253.6167, 270), ((130.63099, 292.7), 90, 106.3833)]:
    msp.add_arc(centre, 3, start, end, dxfattribs=at)
msp.add_point((128.0449, 305.03503), dxfattribs=at)

# ---------------------------------------------------------------- texts
msp.add_text('Yugoslavian M64 7,62 x 39,0', height=6).set_placement((289.99998, 320), align=Align.MIDDLE_CENTER)
at = {"insert": (140.74994, 279.00003), "char_height": 2, "width": 10.5482646, "attachment_point": 2}
msp.add_mtext('\\A1;%%C{\\H0.7x;\\S28,00mm/27,90mm;}', dxfattribs=at)

# ---------------------------------------------------------------- leaders
msp.add_leader([(140.74994, 286.00003), (140.74994, 279.00003)], dimstyle='Standard', override={"dimscale": 1, "dimasz": 2, "dimgap": 0.09, "dimtad": 0, "dimldrblk": 'ClosedBlank'})

doc.saveas('drawing.dxf')
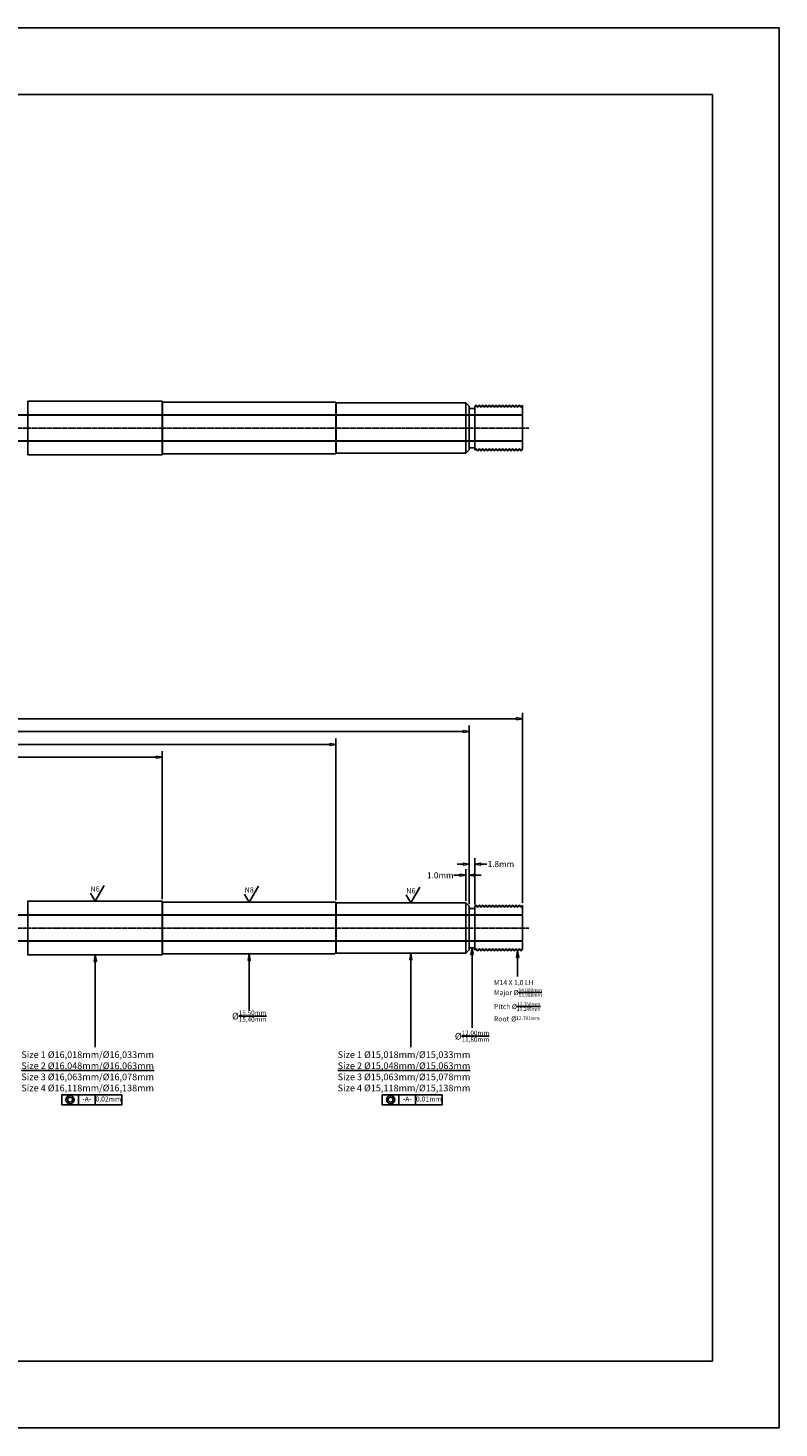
# Model space of a CAD drawing. Units: inches. Extents: x 0 to 594, y 0 to 420.
# Drawn here: x 369 to 594, y 0 to 420 of the extents above; entities that cross this region are included whole.
import ezdxf
from ezdxf.enums import TextEntityAlignment as Align

# ---------------------------------------------------------------- set-up
doc = ezdxf.new("R2010")
doc.units = ezdxf.units.IN
doc.header["$MEASUREMENT"] = 0
doc.linetypes.add('CENTER2', pattern=[1.125, 0.75, -0.125, 0.125, -0.125])
doc.linetypes.add('HIDDEN2', pattern=[0.1875, 0.125, -0.0625])
for name, color, linetype in [('CENTERLINE', 1, 'CENTER2'), ('HIDDEN', 5, 'HIDDEN2'), ('TEXT', 5, 'Continuous')]:
    doc.layers.add(name, color=color, linetype=linetype)
doc.dimstyles.get("Standard").update_dxf_attribs({"dimscale": 10, "dimtxt": 0.18, "dimasz": 0.18, "dimexe": 0.18, "dimexo": 0.0625, "dimgap": 0.09, "dimtad": 0, "dimtih": 1, "dimtoh": 1, "dimdec": 4, "dimzin": 0, "dimdsep": 46, "dimtxsty": 'Standard', "dimblk": 'CLOSEDBLANK', "dimcen": 0.09, "dimadec": 4, "dimazin": 0, "dimtfac": 1, "dimtdec": 4, "dimtofl": 0, "dimtmove": 0, "dimatfit": 3, "dimldrblk": 'CLOSEDBLANK', "dimfxl": 0, "dimtolj": 1, "dimtzin": 0, "dimarcsym": 0})
doc.dimstyles.new('Standard$0', dxfattribs={"dimscale": 10, "dimtxt": 0.18, "dimasz": 0.18, "dimexe": 0.18, "dimexo": 0.0625, "dimgap": 0.09, "dimtad": 0, "dimtih": 1, "dimtoh": 1, "dimdec": 4, "dimzin": 4, "dimdsep": 46, "dimtxsty": 'Standard', "dimblk": 'CLOSEDBLANK', "dimcen": 0.09, "dimadec": 5, "dimazin": 1, "dimtfac": 1, "dimtdec": 4, "dimtofl": 0, "dimtmove": 0, "dimatfit": 3, "dimldrblk": 'CLOSEDBLANK', "dimfxl": 0, "dimtolj": 1, "dimtzin": 0, "dimarcsym": 0})

# ---------------------------------------------------------------- blocks, each defined once
blk = doc.blocks.new('_ClosedBlank')
at = {"color": 0, "linetype": 'ByBlock', "lineweight": -2}
for p, q in [((-1, 0.17), (0, 0)), ((-1, 0.17), (-1, -0.17)), ((0, 0), (-1, -0.17))]:
    blk.add_line(p, q, dxfattribs=at)
blk = doc.blocks.new('*D20')
at = {"color": 0, "lineweight": -2}
for p, q in [((139, 164.63), (139, 210.74)), ((501, 157.15), (501, 210.74)), ((140.8, 208.94), (313.85, 208.94)), ((499.2, 208.94), (326.15, 208.94))]:
    blk.add_line(p, q, dxfattribs=at)
at = {"layer": 'Defpoints', "color": 0}
for p in [(501, 208.94), (139, 164), (501, 156.53)]:
    blk.add_point(p, dxfattribs=at)
at = {"color": 0, "lineweight": -2, "xscale": 1.8, "yscale": 1.8, "zscale": 1.8, "rotation": 180}
blk.add_blockref('_ClosedBlank', (139, 208.94), dxfattribs=at)
at = {"color": 0, "lineweight": -2, "xscale": 1.8, "yscale": 1.8, "zscale": 1.8}
blk.add_blockref('_ClosedBlank', (501, 208.94), dxfattribs=at)
at = {"color": 0, "insert": (320, 208.94), "char_height": 1.8, "attachment_point": 5}
blk.add_mtext('\\A1;362.0mm', dxfattribs=at)
blk = doc.blocks.new('*D17')
at = {"color": 0, "lineweight": -2}
for p, q in [((139, 164.63), (139, 206.89)), ((461, 158.38), (461, 206.89)), ((140.8, 205.09), (293.85, 205.09)), ((459.2, 205.09), (306.15, 205.09))]:
    blk.add_line(p, q, dxfattribs=at)
at = {"layer": 'Defpoints', "color": 0}
for p in [(461, 205.09), (139, 164), (461, 157.75)]:
    blk.add_point(p, dxfattribs=at)
at = {"color": 0, "lineweight": -2, "xscale": 1.8, "yscale": 1.8, "zscale": 1.8, "rotation": 180}
blk.add_blockref('_ClosedBlank', (139, 205.09), dxfattribs=at)
at = {"color": 0, "lineweight": -2, "xscale": 1.8, "yscale": 1.8, "zscale": 1.8}
blk.add_blockref('_ClosedBlank', (461, 205.09), dxfattribs=at)
at = {"color": 0, "insert": (300, 205.09), "char_height": 1.8, "attachment_point": 5}
blk.add_mtext('\\A1;322.0mm', dxfattribs=at)
blk = doc.blocks.new('*D18')
at = {"color": 0, "lineweight": -2}
for p, q in [((499.2, 169.17), (497.4, 169.17)), ((501, 157.15), (501, 170.97)), ((502.75, 157.08), (502.75, 170.97)), ((504.55, 169.17), (506.35, 169.17))]:
    blk.add_line(p, q, dxfattribs=at)
at = {"layer": 'Defpoints', "color": 0}
for p in [(502.75, 169.17), (501, 156.53), (502.75, 156.46)]:
    blk.add_point(p, dxfattribs=at)
at = {"color": 0, "lineweight": -2, "xscale": 1.8, "yscale": 1.8, "zscale": 1.8}
blk.add_blockref('_ClosedBlank', (501, 169.17), dxfattribs=at)
at = {"color": 0, "lineweight": -2, "xscale": 1.8, "yscale": 1.8, "zscale": 1.8, "rotation": 180}
blk.add_blockref('_ClosedBlank', (502.75, 169.17), dxfattribs=at)
at = {"color": 0, "insert": (510.55, 169.17), "char_height": 1.8, "attachment_point": 5}
blk.add_mtext('\\A1;1.8mm', dxfattribs=at)
blk = doc.blocks.new('*D19')
at = {"color": 0, "lineweight": -2}
for p, q in [((498.2, 165.82), (496.4, 165.82)), ((500, 158.15), (500, 167.62)), ((501, 157.15), (501, 167.62)), ((502.8, 165.82), (504.6, 165.82))]:
    blk.add_line(p, q, dxfattribs=at)
at = {"layer": 'Defpoints', "color": 0}
for p in [(500, 165.82), (500, 157.53), (501, 156.53)]:
    blk.add_point(p, dxfattribs=at)
at = {"color": 0, "lineweight": -2, "xscale": 1.8, "yscale": 1.8, "zscale": 1.8}
blk.add_blockref('_ClosedBlank', (500, 165.82), dxfattribs=at)
at = {"color": 0, "lineweight": -2, "xscale": 1.8, "yscale": 1.8, "zscale": 1.8, "rotation": 180}
blk.add_blockref('_ClosedBlank', (501, 165.82), dxfattribs=at)
at = {"color": 0, "insert": (492.35, 165.82), "char_height": 1.8, "attachment_point": 5}
blk.add_mtext('\\A1;1.0mm', dxfattribs=at)
blk = doc.blocks.new('*D24')
at = {"color": 0, "lineweight": -2}
for p, q in [((139, 164.63), (139, 203.03)), ((408.9, 158.65), (408.9, 203.03)), ((140.8, 201.23), (267.65, 201.23)), ((407.1, 201.23), (280.25, 201.23))]:
    blk.add_line(p, q, dxfattribs=at)
at = {"layer": 'Defpoints', "color": 0}
for p in [(139, 201.23), (139, 164), (408.9, 158.03)]:
    blk.add_point(p, dxfattribs=at)
at = {"color": 0, "lineweight": -2, "xscale": 1.8, "yscale": 1.8, "zscale": 1.8, "rotation": 180}
blk.add_blockref('_ClosedBlank', (139, 201.23), dxfattribs=at)
at = {"color": 0, "lineweight": -2, "xscale": 1.8, "yscale": 1.8, "zscale": 1.8}
blk.add_blockref('_ClosedBlank', (408.9, 201.23), dxfattribs=at)
at = {"color": 0, "insert": (273.95, 201.23), "char_height": 1.8, "attachment_point": 5}
blk.add_mtext('\\A1;269.9mm', dxfattribs=at)
blk = doc.blocks.new('*D25')
at = {"color": 0, "lineweight": -2}
for p, q in [((139, 164.63), (139, 214.6)), ((517, 157.52), (517, 214.6)), ((140.8, 212.8), (321.85, 212.8)), ((515.2, 212.8), (334.15, 212.8))]:
    blk.add_line(p, q, dxfattribs=at)
at = {"layer": 'Defpoints', "color": 0}
for p in [(517, 212.8), (139, 164), (517, 156.89)]:
    blk.add_point(p, dxfattribs=at)
at = {"color": 0, "lineweight": -2, "xscale": 1.8, "yscale": 1.8, "zscale": 1.8, "rotation": 180}
blk.add_blockref('_ClosedBlank', (139, 212.8), dxfattribs=at)
at = {"color": 0, "lineweight": -2, "xscale": 1.8, "yscale": 1.8, "zscale": 1.8}
blk.add_blockref('_ClosedBlank', (517, 212.8), dxfattribs=at)
at = {"color": 0, "insert": (328, 212.8), "char_height": 1.8, "attachment_point": 5}
blk.add_mtext('\\A1;378.0mm', dxfattribs=at)

msp = doc.modelspace()

# ---------------------------------------------------------------- linework, layer by layer
for p, q in [((368.59994, 308.02503), (408.89994, 308.02503)), ((368.59994, 308.02503), (368.59994, 291.97503)), ((408.89994, 291.97503), (408.89994, 308.02503)), ((408.99994, 307.75003), (460.99994, 307.75003)), ((408.99994, 307.75003), (408.99994, 292.25003)), ((460.99994, 292.25003), (460.99994, 307.75003)), ((461.09994, 307.52503), (499.99994, 307.52503)), ((461.09994, 307.52503), (461.09994, 292.47503)), ((499.99994, 292.47503), (499.99994, 307.52503)), ((499.99994, 307.52503), (500.99994, 306.52503)), ((502.74994, 306.45876), (502.99994, 306.89178)), ((502.99994, 306.89178), (503.12494, 306.89178)), ((503.12494, 306.89178), (503.52077, 306.20617)), ((503.6041, 306.20617), (503.99994, 306.89178)), ((503.99994, 306.89178), (504.12494, 306.89178)), ((504.12494, 306.89178), (504.52077, 306.20617)), ((504.6041, 306.20617), (504.99994, 306.89178)), ((504.99994, 306.89178), (505.12494, 306.89178)), ((505.12494, 306.89178), (505.52077, 306.20617)), ((505.6041, 306.20617), (505.99994, 306.89178)), ((505.99994, 306.89178), (506.12494, 306.89178)), ((506.12494, 306.89178), (506.52077, 306.20617)), ((506.6041, 306.20617), (506.99994, 306.89178)), ((506.99994, 306.89178), (507.12494, 306.89178)), ((507.12494, 306.89178), (507.52077, 306.20617)), ((507.6041, 306.20617), (507.99994, 306.89178)), ((507.99994, 306.89178), (508.12494, 306.89178)), ((508.12494, 306.89178), (508.52077, 306.20617)), ((508.6041, 306.20617), (508.99994, 306.89178)), ((508.99994, 306.89178), (509.12494, 306.89178)), ((509.12494, 306.89178), (509.52077, 306.20617)), ((509.6041, 306.20617), (509.99994, 306.89178)), ((509.99994, 306.89178), (510.12494, 306.89178)), ((510.12494, 306.89178), (510.52077, 306.20617)), ((510.6041, 306.20617), (510.99994, 306.89178)), ((510.99994, 306.89178), (511.12494, 306.89178)), ((511.12494, 306.89178), (511.52077, 306.20617)), ((511.6041, 306.20617), (511.99994, 306.89178)), ((511.99994, 306.89178), (512.12494, 306.89178)), ((512.12494, 306.89178), (512.52077, 306.20617)), ((512.6041, 306.20617), (512.99994, 306.89178)), ((512.99994, 306.89178), (513.12494, 306.89178)), ((513.12494, 306.89178), (513.52077, 306.20617)), ((513.6041, 306.20617), (513.99994, 306.89178)), ((513.99994, 306.89178), (514.12494, 306.89178)), ((514.12494, 306.89178), (514.52077, 306.20617)), ((514.6041, 306.20617), (514.99994, 306.89178)), ((514.99994, 306.89178), (515.12494, 306.89178)), ((515.12494, 306.89178), (515.52077, 306.20617)), ((515.6041, 306.20617), (515.99994, 306.89178)), ((515.99994, 306.89178), (516.12494, 306.89178)), ((516.12494, 306.89178), (516.52077, 306.20617)), ((516.6041, 306.20617), (516.99994, 306.89178)), ((516.99994, 306.89178), (516.99994, 293.7578)), ((500.99994, 293.47503), (500.99994, 306.52503)), ((500.99994, 305.90003), (502.74994, 305.90003)), ((502.74994, 293.32479), (502.74994, 306.45876)), ((503.49994, 306.24226), (503.52077, 306.20617)), ((503.52077, 306.20617), (503.6041, 306.20617)), ((503.6041, 306.20617), (503.52077, 306.20617)), ((504.49994, 306.24226), (504.52077, 306.20617)), ((504.52077, 306.20617), (504.6041, 306.20617)), ((504.6041, 306.20617), (504.52077, 306.20617)), ((505.52077, 306.20617), (505.6041, 306.20617)), ((505.6041, 306.20617), (505.52077, 306.20617)), ((506.6041, 306.20617), (506.52077, 306.20617)), ((507.6041, 306.20617), (507.52077, 306.20617)), ((508.6041, 306.20617), (508.52077, 306.20617)), ((509.6041, 306.20617), (509.52077, 306.20617)), ((510.6041, 306.20617), (510.52077, 306.20617)), ((511.6041, 306.20617), (511.52077, 306.20617)), ((512.6041, 306.20617), (512.52077, 306.20617)), ((513.6041, 306.20617), (513.52077, 306.20617)), ((514.6041, 306.20617), (514.52077, 306.20617)), ((515.6041, 306.20617), (515.52077, 306.20617)), ((516.6041, 306.20617), (516.52077, 306.20617)), ((500.99994, 294.10003), (502.74994, 294.10003)), ((368.59994, 291.97503), (408.89994, 291.97503)), ((408.99994, 292.25003), (460.99994, 292.25003)), ((461.09994, 292.47503), (499.99994, 292.47503)), ((499.99994, 292.47503), (500.99994, 293.47503)), ((502.74994, 293.32479), (503.02077, 293.79389)), ((503.02077, 293.79389), (503.1041, 293.79389)), ((503.1041, 293.79389), (503.02077, 293.79389)), ((503.1041, 293.79389), (503.49994, 293.10828)), ((503.49994, 293.10828), (503.62494, 293.10828)), ((503.62494, 293.10828), (504.02077, 293.79389)), ((504.02077, 293.79389), (504.1041, 293.79389)), ((504.1041, 293.79389), (504.02077, 293.79389)), ((504.1041, 293.79389), (504.49994, 293.10828)), ((504.49994, 293.10828), (504.62494, 293.10828)), ((504.62494, 293.10828), (505.02077, 293.79389)), ((505.02077, 293.79389), (505.1041, 293.79389)), ((505.1041, 293.79389), (505.02077, 293.79389)), ((505.1041, 293.79389), (505.49994, 293.10828)), ((505.49994, 293.10828), (505.62494, 293.10828)), ((505.62494, 293.10828), (506.02077, 293.79389)), ((506.1041, 293.79389), (506.02077, 293.79389)), ((506.1041, 293.79389), (506.49994, 293.10828)), ((506.49994, 293.10828), (506.62494, 293.10828)), ((506.62494, 293.10828), (507.02077, 293.79389)), ((507.1041, 293.79389), (507.02077, 293.79389)), ((507.1041, 293.79389), (507.49994, 293.10828)), ((507.49994, 293.10828), (507.62494, 293.10828)), ((507.62494, 293.10828), (508.02077, 293.79389)), ((508.1041, 293.79389), (508.02077, 293.79389)), ((508.1041, 293.79389), (508.49994, 293.10828)), ((508.49994, 293.10828), (508.62494, 293.10828)), ((508.62494, 293.10828), (509.02077, 293.79389)), ((509.1041, 293.79389), (509.02077, 293.79389)), ((509.1041, 293.79389), (509.49994, 293.10828)), ((509.49994, 293.10828), (509.62494, 293.10828)), ((509.62494, 293.10828), (510.02077, 293.79389)), ((510.1041, 293.79389), (510.02077, 293.79389)), ((510.1041, 293.79389), (510.49994, 293.10828)), ((510.49994, 293.10828), (510.62494, 293.10828)), ((510.62494, 293.10828), (511.02077, 293.79389)), ((511.1041, 293.79389), (511.02077, 293.79389)), ((511.1041, 293.79389), (511.49994, 293.10828)), ((511.49994, 293.10828), (511.62494, 293.10828)), ((511.62494, 293.10828), (512.02077, 293.79389)), ((512.1041, 293.79389), (512.02077, 293.79389)), ((512.1041, 293.79389), (512.49994, 293.10828)), ((512.49994, 293.10828), (512.62494, 293.10828)), ((512.62494, 293.10828), (513.02077, 293.79389)), ((513.1041, 293.79389), (513.02077, 293.79389)), ((513.1041, 293.79389), (513.49994, 293.10828)), ((513.49994, 293.10828), (513.62494, 293.10828)), ((513.62494, 293.10828), (514.02077, 293.79389)), ((514.1041, 293.79389), (514.02077, 293.79389)), ((514.1041, 293.79389), (514.49994, 293.10828)), ((514.49994, 293.10828), (514.62494, 293.10828)), ((514.62494, 293.10828), (515.02077, 293.79389)), ((515.1041, 293.79389), (515.02077, 293.79389)), ((515.1041, 293.79389), (515.49994, 293.10828)), ((515.49994, 293.10828), (515.62494, 293.10828)), ((515.62494, 293.10828), (516.02077, 293.79389)), ((516.1041, 293.79389), (516.02077, 293.79389)), ((516.1041, 293.79389), (516.49994, 293.10828)), ((516.49994, 293.10828), (516.62494, 293.10828)), ((516.62494, 293.10828), (516.99994, 293.7578)), ((387.37514, 160.40628), (388.74996, 158.02503)), ((388.74996, 158.02503), (391.49959, 162.78753)), ((433.62514, 160.13128), (434.99996, 157.75003)), ((434.99996, 157.75003), (437.74959, 162.51253)), ((482.12514, 159.90628), (483.49996, 157.52503)), ((483.49996, 157.52503), (486.24959, 162.28753)), ((368.59996, 158.02503), (408.89996, 158.02503)), ((368.59996, 158.02503), (368.59996, 141.97503)), ((408.89996, 141.97503), (408.89996, 158.02503)), ((408.99996, 157.75003), (460.99996, 157.75003)), ((408.99996, 157.75003), (408.99996, 142.25003)), ((460.99996, 142.25003), (460.99996, 157.75003)), ((461.09996, 157.52503), (499.99996, 157.52503)), ((461.09996, 157.52503), (461.09996, 142.47503)), ((499.99996, 142.47503), (499.99996, 157.52503)), ((499.99996, 157.52503), (500.99996, 156.52503)), ((500.99996, 143.47503), (500.99996, 156.52503)), ((500.99996, 155.90003), (502.74996, 155.90003)), ((502.74996, 156.45876), (502.99996, 156.89178)), ((502.74996, 143.32479), (502.74996, 156.45876)), ((502.99996, 156.89178), (503.12496, 156.89178)), ((503.12496, 156.89178), (503.52079, 156.20617)), ((503.49996, 156.24226), (503.52079, 156.20617)), ((503.52079, 156.20617), (503.60413, 156.20617)), ((503.60413, 156.20617), (503.52079, 156.20617)), ((503.60413, 156.20617), (503.99996, 156.89178)), ((503.99996, 156.89178), (504.12496, 156.89178)), ((504.12496, 156.89178), (504.52079, 156.20617)), ((504.49996, 156.24226), (504.52079, 156.20617)), ((504.52079, 156.20617), (504.60413, 156.20617)), ((504.60413, 156.20617), (504.52079, 156.20617)), ((504.60413, 156.20617), (504.99996, 156.89178)), ((504.99996, 156.89178), (505.12496, 156.89178)), ((505.12496, 156.89178), (505.52079, 156.20617)), ((505.52079, 156.20617), (505.60413, 156.20617)), ((505.60413, 156.20617), (505.52079, 156.20617)), ((505.60413, 156.20617), (505.99996, 156.89178)), ((505.99996, 156.89178), (506.12496, 156.89178)), ((506.12496, 156.89178), (506.52079, 156.20617)), ((506.60413, 156.20617), (506.52079, 156.20617)), ((506.60413, 156.20617), (506.99996, 156.89178)), ((506.99996, 156.89178), (507.12496, 156.89178)), ((507.12496, 156.89178), (507.52079, 156.20617)), ((507.60413, 156.20617), (507.52079, 156.20617)), ((507.60413, 156.20617), (507.99996, 156.89178)), ((507.99996, 156.89178), (508.12496, 156.89178)), ((508.12496, 156.89178), (508.52079, 156.20617)), ((508.60413, 156.20617), (508.52079, 156.20617)), ((508.60413, 156.20617), (508.99996, 156.89178)), ((508.99996, 156.89178), (509.12496, 156.89178)), ((509.12496, 156.89178), (509.52079, 156.20617)), ((509.60413, 156.20617), (509.52079, 156.20617)), ((509.60413, 156.20617), (509.99996, 156.89178)), ((509.99996, 156.89178), (510.12496, 156.89178)), ((510.12496, 156.89178), (510.52079, 156.20617)), ((510.60413, 156.20617), (510.52079, 156.20617)), ((510.60413, 156.20617), (510.99996, 156.89178)), ((510.99996, 156.89178), (511.12496, 156.89178)), ((511.12496, 156.89178), (511.52079, 156.20617)), ((511.60413, 156.20617), (511.52079, 156.20617)), ((511.60413, 156.20617), (511.99996, 156.89178)), ((511.99996, 156.89178), (512.12496, 156.89178)), ((512.12496, 156.89178), (512.52079, 156.20617)), ((512.60413, 156.20617), (512.52079, 156.20617)), ((512.60413, 156.20617), (512.99996, 156.89178)), ((512.99996, 156.89178), (513.12496, 156.89178)), ((513.12496, 156.89178), (513.52079, 156.20617)), ((513.60413, 156.20617), (513.52079, 156.20617)), ((513.60413, 156.20617), (513.99996, 156.89178)), ((513.99996, 156.89178), (514.12496, 156.89178)), ((514.12496, 156.89178), (514.52079, 156.20617)), ((514.60413, 156.20617), (514.52079, 156.20617)), ((514.60413, 156.20617), (514.99996, 156.89178)), ((514.99996, 156.89178), (515.12496, 156.89178)), ((515.12496, 156.89178), (515.52079, 156.20617)), ((515.60413, 156.20617), (515.52079, 156.20617)), ((515.60413, 156.20617), (515.99996, 156.89178)), ((515.99996, 156.89178), (516.12496, 156.89178)), ((516.12496, 156.89178), (516.52079, 156.20617)), ((516.60413, 156.20617), (516.52079, 156.20617)), ((516.60413, 156.20617), (516.99996, 156.89178)), ((516.99996, 156.89178), (516.99996, 143.7578)), ((499.99996, 142.47503), (500.99996, 143.47503)), ((500.99996, 144.10003), (502.74996, 144.10003)), ((502.74996, 143.32479), (503.02079, 143.79389)), ((503.02079, 143.79389), (503.10413, 143.79389)), ((503.10413, 143.79389), (503.02079, 143.79389)), ((503.10413, 143.79389), (503.49996, 143.10828)), ((503.49996, 143.10828), (503.62496, 143.10828)), ((503.62496, 143.10828), (504.02079, 143.79389)), ((504.02079, 143.79389), (504.10413, 143.79389)), ((504.10413, 143.79389), (504.02079, 143.79389)), ((504.10413, 143.79389), (504.49996, 143.10828)), ((504.49996, 143.10828), (504.62496, 143.10828)), ((504.62496, 143.10828), (505.02079, 143.79389)), ((505.02079, 143.79389), (505.10413, 143.79389)), ((505.10413, 143.79389), (505.02079, 143.79389)), ((505.10413, 143.79389), (505.49996, 143.10828)), ((505.49996, 143.10828), (505.62496, 143.10828)), ((505.62496, 143.10828), (506.02079, 143.79389)), ((506.10413, 143.79389), (506.02079, 143.79389)), ((506.10413, 143.79389), (506.49996, 143.10828)), ((506.49996, 143.10828), (506.62496, 143.10828)), ((506.62496, 143.10828), (507.02079, 143.79389)), ((507.10413, 143.79389), (507.02079, 143.79389)), ((507.10413, 143.79389), (507.49996, 143.10828)), ((507.49996, 143.10828), (507.62496, 143.10828)), ((507.62496, 143.10828), (508.02079, 143.79389)), ((508.10413, 143.79389), (508.02079, 143.79389)), ((508.10413, 143.79389), (508.49996, 143.10828)), ((508.49996, 143.10828), (508.62496, 143.10828)), ((508.62496, 143.10828), (509.02079, 143.79389)), ((509.10413, 143.79389), (509.02079, 143.79389)), ((509.10413, 143.79389), (509.49996, 143.10828)), ((509.49996, 143.10828), (509.62496, 143.10828)), ((509.62496, 143.10828), (510.02079, 143.79389)), ((510.10413, 143.79389), (510.02079, 143.79389)), ((510.10413, 143.79389), (510.49996, 143.10828)), ((510.49996, 143.10828), (510.62496, 143.10828)), ((510.62496, 143.10828), (511.02079, 143.79389)), ((511.10413, 143.79389), (511.02079, 143.79389)), ((511.10413, 143.79389), (511.49996, 143.10828)), ((511.49996, 143.10828), (511.62496, 143.10828)), ((511.62496, 143.10828), (512.02079, 143.79389)), ((512.10413, 143.79389), (512.02079, 143.79389)), ((512.10413, 143.79389), (512.49996, 143.10828)), ((512.49996, 143.10828), (512.62496, 143.10828)), ((512.62496, 143.10828), (513.02079, 143.79389)), ((513.10413, 143.79389), (513.02079, 143.79389)), ((513.10413, 143.79389), (513.49996, 143.10828)), ((513.49996, 143.10828), (513.62496, 143.10828)), ((513.62496, 143.10828), (514.02079, 143.79389)), ((514.10413, 143.79389), (514.02079, 143.79389)), ((514.10413, 143.79389), (514.49996, 143.10828)), ((514.49996, 143.10828), (514.62496, 143.10828)), ((514.62496, 143.10828), (515.02079, 143.79389)), ((515.10413, 143.79389), (515.02079, 143.79389)), ((515.10413, 143.79389), (515.49996, 143.10828)), ((515.49996, 143.10828), (515.62496, 143.10828)), ((515.62496, 143.10828), (516.02079, 143.79389)), ((516.10413, 143.79389), (516.02079, 143.79389)), ((516.10413, 143.79389), (516.49996, 143.10828)), ((516.49996, 143.10828), (516.62496, 143.10828)), ((516.62496, 143.10828), (516.99996, 143.7578)), ((368.59996, 141.97503), (408.89996, 141.97503)), ((408.99996, 142.25003), (460.72996, 142.25003)), ((460.82996, 142.47503), (499.99996, 142.47503))]:
    msp.add_line(p, q)
for points in [[(-0.00002, 0.00005), (593.99998, 0.00005), (593.99998, 420.00005), (-0.00002, 420.00005)], [(19.99998, 20.00005), (573.99998, 20.00005), (573.99998, 400.00005), (19.99998, 400.00005)]]:
    msp.add_lwpolyline(points, close=True)
for centre, start, end in [((408.99994, 307.85003), 180, 270), ((461.09994, 307.62503), 180, 270), ((408.99994, 292.15003), 90, 180), ((461.09994, 292.37503), 90, 180), ((368.59996, 158.12503), 180, 270), ((408.99996, 157.85003), 180, 270), ((461.09996, 157.62503), 180, 270), ((368.59996, 141.87503), 90, 180), ((408.99996, 142.15003), 90, 180), ((461.09996, 142.37503), 90, 180)]:
    msp.add_arc(centre, 0.1, start, end)
at = {"layer": 'CENTERLINE'}
for p, q in [((98.49994, 300.00003), (518.99998, 300.00003)), ((98.49996, 150.00003), (518.99996, 150.00003))]:
    msp.add_line(p, q, dxfattribs=at)
at = {"layer": 'HIDDEN'}
for p, q in [((136.58247, 303.96243), (516.99994, 303.96243)), ((136.73487, 303.81003), (516.99994, 303.81003)), ((136.58254, 296.03763), (516.99994, 296.03763)), ((136.73494, 296.19003), (516.99994, 296.19003)), ((136.5825, 153.96243), (516.99996, 153.96243)), ((136.7349, 153.81003), (516.99996, 153.81003)), ((136.58256, 146.03763), (516.99996, 146.03763)), ((136.73496, 146.19003), (516.99996, 146.19003))]:
    msp.add_line(p, q, dxfattribs=at)
at = {"layer": 'TEXT', "color": 7}
for p, q in [((378.72424, 97), (378.72424, 100)), ((378.72424, 100), (383.72424, 100)), ((378.72424, 97), (383.72424, 97)), ((383.72424, 100), (388.72424, 100)), ((383.72424, 97), (383.72424, 100)), ((383.72424, 97), (388.72424, 97)), ((388.72424, 100), (396.72424, 100)), ((388.72424, 97), (388.72424, 100)), ((388.72424, 97), (396.72424, 97)), ((396.72424, 97), (396.72424, 100)), ((474.93457, 97), (474.93457, 100)), ((474.93457, 100), (479.93457, 100)), ((474.93457, 97), (479.93457, 97)), ((479.93457, 100), (484.93457, 100)), ((479.93457, 97), (479.93457, 100)), ((479.93457, 97), (484.93457, 97)), ((484.93457, 100), (492.93457, 100)), ((484.93457, 97), (484.93457, 100)), ((484.93457, 97), (492.93457, 97)), ((492.93457, 97), (492.93457, 100))]:
    msp.add_line(p, q, dxfattribs=at)
for centre, radius in [((381.22424, 98.5), 1.25), ((381.22424, 98.5), 0.75), ((477.43457, 98.5), 1.25), ((477.43457, 98.5), 0.75)]:
    msp.add_circle(centre, radius, dxfattribs=at)

# ---------------------------------------------------------------- texts
for s, p in [('N6', (388.74996, 160.40628)), ('N8', (434.99996, 160.13128)), ('N6', (483.49996, 159.90628))]:
    msp.add_text(s, height=1.5875).set_placement(p, align=Align.BOTTOM_CENTER)
at = {"char_height": 2, "width": 10.5482646, "attachment_point": 2}
for s, insert in [('\\A1;%%C{\\H0.7x;\\S15,50mm/15,40mm;}', (434.99996, 125.25003)), ('\\A1;%%C{\\H0.7x;\\S12,00mm/11,80mm;}', (501.87496, 119.21478))]:
    msp.add_mtext(s, dxfattribs=dict(at, insert=insert))
at = {"layer": 'TEXT', "color": 7}
for s, insert, char_height, width, attachment_point in [('\\A1;{\\H0.75x;M14 X 1,0 LH\\PMajor %%C\\H0.7x;\\S14,000mm/13,988mm;\\H1.429x;\\PPitch %%C\\H0.7x;\\S13,350mm/13,240mm;\\H1.429x;\\PRoot} {\\H0.75x;%%C\\H0.7x;12,701mm}', (508.45201, 134.37094), 2, 19.3860592, 1), ('\\A1;Size 1 %%C16,018mm/%%C16,033mm\\P{\\LSize 2 %%C16,048mm/%%C16,063mm}\\PSize 3 %%C16,063mm/%%C16,078mm\\PSize 4 %%C16,118mm/%%C16,138mm', (366.61639, 113), 2, 48.5376086, 1), ('\\A1;Size 1 %%C15,018mm/%%C15,033mm\\P{\\LSize 2 %%C15,048mm/%%C15,063mm}\\PSize 3 %%C15,063mm/%%C15,078mm\\PSize 4 %%C15,118mm/%%C15,138mm', (461.54314, 113), 2, 48.5376086, 1), ('-A-', (386.22424, 98.5), 1.5, 1.19634, 5), ('0,02mm', (392.72424, 98.5), 1.5, 6.6720954, 5), ('-A-', (482.43457, 98.5), 1.5, 1.19634, 5), ('0,01mm', (488.93457, 98.5), 1.5, 6.6720954, 5)]:
    msp.add_mtext(s, dxfattribs=dict(at, insert=insert, char_height=char_height, width=width, attachment_point=attachment_point))

# ---------------------------------------------------------------- dimensions: what is measured, and where the dimension line sits
for base, p1, p2, picture, middle in [((516.99996, 212.7953), (138.99996, 164.00003), (516.99996, 156.89178), '*D25', (327.99996, 212.7953)), ((500.99996, 208.94125), (138.99996, 164.00003), (500.99996, 156.52503), '*D20', (319.99996, 208.94125)), ((460.99996, 205.08719), (138.99996, 164.00003), (460.99996, 157.75003), '*D17', (299.99996, 205.08719)), ((138.99996, 201.23314), (408.89996, 158.02503), (138.99996, 164.00003), '*D24', (273.94996, 201.23314)), ((502.749960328, 169.1660716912), (500.999960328, 156.5250289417), (502.749960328, 156.4587630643), '*D18', (510.549960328, 169.1660716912))]:
    dim = msp.add_linear_dim(base=base, p1=p1, p2=p2, dimstyle='Standard$0', override={"dimscale": 10, "dimdec": 1, "dimpost": 'mm', "dimblk1": 'ClosedBlank', "dimblk2": 'ClosedBlank', "dimsah": 1})
    dim.commit()
    dim.dimension.update_dxf_attribs({"geometry": picture, "text_midpoint": middle})
dim = msp.add_linear_dim(base=(499.99996, 165.81887), p1=(500.99996, 156.52503), p2=(499.99996, 157.52503), angle=180, dimstyle='Standard$0', override={"dimscale": 10, "dimdec": 1, "dimpost": 'mm', "dimblk1": 'ClosedBlank', "dimblk2": 'ClosedBlank', "dimsah": 1})
dim.commit()
dim.dimension.update_dxf_attribs({"geometry": '*D19', "text_midpoint": (492.34996, 165.81887)})

# ---------------------------------------------------------------- leaders
for points in [[(501.87496, 144.10003), (501.87496, 120.08332)], [(515.56246, 143.10828), (515.56246, 135.45928)], [(434.99996, 142.25003), (434.99996, 125.25003)]]:
    msp.add_leader(points, dimstyle='Standard', override={"dimscale": 1, "dimasz": 2, "dimgap": 0.09, "dimtad": 0, "dimldrblk": 'ClosedBlank'})
for points in [[(388.79996, 141.97503), (388.79996, 114.23901)], [(483.49996, 142.47503), (483.49996, 114.23901)]]:
    msp.add_leader(points, dimstyle='Standard', override={"dimscale": 1, "dimasz": 2, "dimgap": 0.09, "dimtad": 0, "dimldrblk": 'ClosedBlank'}, dxfattribs=at)

doc.saveas('drawing.dxf')
